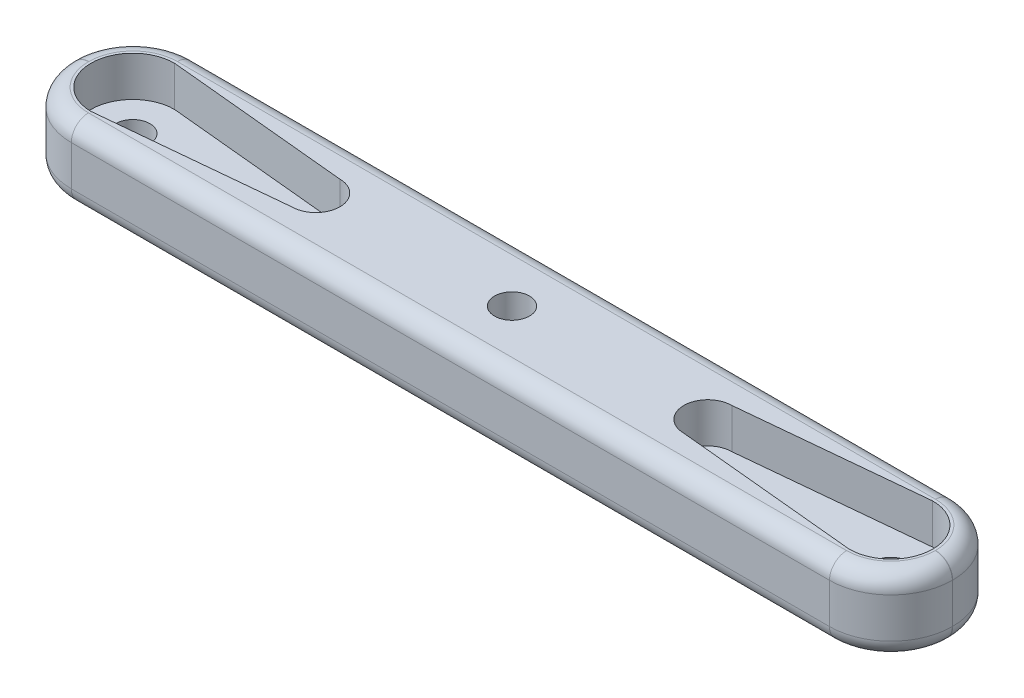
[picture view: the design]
from build123d import *

# Parameters (mm, degrees)
SKETCH1_W           = 77
SKETCH1_H           = 10.77
BOSS_EXTRUDE1_DEPTH = 6.5
SKETCH2_R           = 1.5
CUT_EXTRUDE1_DEPTH  = 3.5
SKETCH4_R           = 1.5
CUT_EXTRUDE4_DEPTH  = 40.414441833
CUT_EXTRUDE5_DEPTH  = 3.5
CUT_EXTRUDE6_DEPTH  = 40.414441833
SKETCH5_R           = 1.525
CUT_EXTRUDE7_DEPTH  = 40.414441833
FILLET1_R           = 1.5
SKETCH6_W           = 0.628205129
SKETCH6_H           = 2.557692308
SKETCH6_W_2         = 0.246794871
SKETCH6_H_2         = 2.009615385
CUT_EXTRUDE8_DEPTH  = 1


with BuildPart() as part:
    # Sketch1 → Boss-Extrude1 (new body)
    with BuildSketch(Plane(origin=(0, 0, 0), x_dir=(1, 0, 0), z_dir=(0, 1, 0))):
        Rectangle(SKETCH1_W, SKETCH1_H)
    extrude(amount=BOSS_EXTRUDE1_DEPTH)

    # Sketch2 → Cut-Extrude1 (cut)
    # profile 1 of 2: a face of its own
    with BuildSketch(Plane(origin=(0, 6.5, 0), x_dir=(1, 0, 0), z_dir=(0, 1, 0))):
        with BuildLine():
            ThreePointArc((-32.429387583, -3.597128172), (-30.312222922, -2.335050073), (-29.48, -0.015))
            ThreePointArc((-29.48, -0.015), (-30.312222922, 2.305050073), (-32.429387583, 3.567128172))
            Line((-32.429387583, 3.567128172), (-33.13, 3.635))
            ThreePointArc((-33.13, 3.635), (-36.78, -0.015), (-33.13, -3.665))
            Line((-33.13, -3.665), (-32.429387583, -3.597128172))
        make_face()
        with Locations(Location((-33.13, -0.015, 0), (0, 0, 270))):
            Circle(SKETCH2_R, mode=Mode.SUBTRACT)
    # profile 2 of 2: a face of its own
    with BuildSketch(Plane(origin=(0, 6.5, 0), x_dir=(1, 0, 0), z_dir=(0, 1, 0))):
        with BuildLine():
            ThreePointArc((32.429387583, 3.567128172), (30.312222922, 2.305050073), (29.48, -0.015))
            ThreePointArc((29.48, -0.015), (30.312222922, -2.335050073), (32.429387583, -3.597128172))
            Line((32.429387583, -3.597128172), (33.13, -3.665))
            ThreePointArc((33.13, -3.665), (36.78, -0.015), (33.13, 3.635))
            Line((33.13, 3.635), (32.429387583, 3.567128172))
        make_face()
        with Locations(Location((33.13, -0.015, 0), (0, 0, 270))):
            Circle(SKETCH2_R, mode=Mode.SUBTRACT)
    extrude(amount=-CUT_EXTRUDE1_DEPTH, mode=Mode.SUBTRACT)

    # Sketch4 → Cut-Extrude4 (cut, through all)
    with BuildSketch(Plane(origin=(0, 6.5, 0), x_dir=(1, 0, 0), z_dir=(0, 1, 0))):
        with Locations(Location((-33.13, -0.015, 0), (0, 0, 270))):
            Circle(SKETCH4_R)
        with Locations(Location((33.13, -0.015, 0), (0, 0, 270))):
            Circle(SKETCH4_R)
    extrude(amount=-CUT_EXTRUDE4_DEPTH, mode=Mode.SUBTRACT)

    # Sketch2_5 → Cut-Extrude5 (cut)
    with BuildSketch(Plane(origin=(0, 6.5, 0), x_dir=(1, 0, 0), z_dir=(0, 1, 0))):
        with BuildLine():
            ThreePointArc((-32.429387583, 3.567128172), (-29.48, -0.015), (-32.429387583, -3.597128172))
            Line((-32.429387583, -3.597128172), (-17.13, -2.115))
            ThreePointArc((-17.13, -2.115), (-15.03, -0.015), (-17.13, 2.085))
            Line((-17.13, 2.085), (-32.429387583, 3.567128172))
        make_face()
        with BuildLine():
            ThreePointArc((32.429387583, -3.597128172), (29.48, -0.015), (32.429387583, 3.567128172))
            Line((32.429387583, 3.567128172), (17.13, 2.085))
            ThreePointArc((17.13, 2.085), (15.03, -0.015), (17.13, -2.115))
            Line((17.13, -2.115), (32.429387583, -3.597128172))
        make_face()
    extrude(amount=-CUT_EXTRUDE5_DEPTH, mode=Mode.SUBTRACT)

    # Sketch2_6 → Cut-Extrude6 (cut, through all)
    with BuildSketch(Plane(origin=(0, 6.5, 0), x_dir=(1, 0, 0), z_dir=(0, 1, 0))):
        with BuildLine():
            Line((-38.5, 5.385), (-38.5, 0.015))
            ThreePointArc((-38.5, 0.015), (-36.927163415, 3.812163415), (-33.13, 5.385))
            Line((-33.13, 5.385), (-38.5, 5.385))
        make_face()
        with BuildLine():
            Line((-38.5, -5.385), (-33.13, -5.385))
            ThreePointArc((-33.13, -5.385), (-36.927163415, -3.812163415), (-38.5, -0.015))
            Line((-38.5, -0.015), (-38.5, -5.385))
        make_face()
        with BuildLine():
            ThreePointArc((38.5, -0.015), (36.927163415, -3.812163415), (33.13, -5.385))
            Line((33.13, -5.385), (38.5, -5.385))
            Line((38.5, -5.385), (38.5, -0.015))
        make_face()
        with BuildLine():
            ThreePointArc((33.13, 5.385), (36.927163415, 3.812163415), (38.5, 0.015))
            Line((38.5, 0.015), (38.5, 5.385))
            Line((38.5, 5.385), (33.13, 5.385))
        make_face()
    extrude(amount=-CUT_EXTRUDE6_DEPTH, mode=Mode.SUBTRACT)

    # Sketch5 → Cut-Extrude7 (cut, through all)
    with BuildSketch(Plane(origin=(0, 6.5, 0), x_dir=(1, 0, 0), z_dir=(0, 1, 0))):
        with Locations(Location((0, 0, 0), (0, 0, 270))):
            Circle(SKETCH5_R)
    extrude(amount=-CUT_EXTRUDE7_DEPTH, mode=Mode.SUBTRACT)

    # Fillet1
    fillet1_edges = [part.edges().sort_by_distance(p)[0] for p in [
        (-36.927163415, 6.5, 3.812163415),
        (-36.927163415, 0, 3.812163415),
        (-36.927163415, 6.5, -3.812163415),
        (-36.927163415, 0, -3.812163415),
        (38.5, 0, 0),
        (0, 0, 5.385),
        (-38.5, 0, 0),
        (0, 0, -5.385),
        (0, 6.5, 5.385),
        (-38.5, 6.5, 0),
        (0, 6.5, -5.385),
        (38.5, 6.5, 0),
        (36.927163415, 6.5, -3.812163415),
        (36.927163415, 0, -3.812163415),
        (36.927163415, 0, 3.812163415),
        (36.927163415, 6.5, 3.812163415),
    ]]
    fillet(fillet1_edges, radius=FILLET1_R)

    # Sketch6 → Cut-Extrude8 (cut)
    # profile 1 of 21: a face of its own
    with BuildSketch(Plane.XZ):
        Polygon((-30.093520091, 1.617771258), (-29.441476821, 1.617771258), (-28.642899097, -0.823534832), (-27.838712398, 1.617771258), (-27.192979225, 1.617771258), (-26.60123243, -1.882228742), (-27.237149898, -1.882228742), (-27.610847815, 0.328408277), (-28.338612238, -1.882228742), (-28.951392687, -1.882228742), (-29.674950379, 0.328408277), (-30.047947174, -1.882228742), (-30.684565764, -1.882228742), align=None)
    # profile 2 of 21: a face of its own
    with BuildSketch(Plane.XZ):
        with BuildLine():
            add(Edge.make_bspline(
                [(-25.839814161, 1.752386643), (-25.812738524, 1.75105821), (-25.759572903, 1.748449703), (-25.683405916, 1.723022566), (-25.613500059, 1.683115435), (-25.551701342, 1.6283619), (-25.500302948, 1.562976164), (-25.461032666, 1.489772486), (-25.439156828, 1.408665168), (-25.436118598, 1.352637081), (-25.434565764, 1.324001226)],
                knots=[0, 0, 0, 0, 0.989868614, 1.943702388, 2.910836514, 3.924849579, 4.949916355, 5.946401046, 6.950409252, 8, 8, 8, 8], degree=3))
            add(Edge.make_bspline(
                [(-25.434565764, 1.324001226), (-25.43606304, 1.295576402), (-25.438980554, 1.240189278), (-25.461536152, 1.160183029), (-25.499230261, 1.087014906), (-25.55104495, 1.02260027), (-25.612173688, 0.968728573), (-25.680552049, 0.928096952), (-25.755989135, 0.904084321), (-25.808329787, 0.901257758), (-25.834906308, 0.89982254)],
                knots=[0, 0, 0, 0, 1.05296456, 2.051751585, 3.055639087, 4.085634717, 5.099016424, 6.062201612, 7.016062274, 8, 8, 8, 8], degree=3))
            add(Edge.make_bspline(
                [(-25.834906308, 0.89982254), (-25.862218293, 0.901146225), (-25.915846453, 0.903745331), (-25.992638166, 0.929231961), (-26.063476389, 0.968824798), (-26.125007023, 1.024697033), (-26.176994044, 1.090547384), (-26.214548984, 1.165455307), (-26.238040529, 1.247117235), (-26.240828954, 1.303975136), (-26.242258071, 1.333115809)],
                knots=[0, 0, 0, 0, 0.989065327, 1.942068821, 2.907541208, 3.917690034, 4.939857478, 5.938239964, 6.943311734, 8, 8, 8, 8], degree=3))
            add(Edge.make_bspline(
                [(-26.242258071, 1.333115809), (-26.240702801, 1.361057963), (-26.237647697, 1.415946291), (-26.21564082, 1.495250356), (-26.177271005, 1.567223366), (-26.126242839, 1.631412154), (-26.064986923, 1.68514433), (-25.995123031, 1.723839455), (-25.91946865, 1.748216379), (-25.866639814, 1.750982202), (-25.839814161, 1.752386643)],
                knots=[0, 0, 0, 0, 1.038616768, 2.040212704, 3.031499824, 4.052181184, 5.074969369, 6.039807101, 7.004644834, 8, 8, 8, 8], degree=3))
        make_face()
    # profile 3 of 21: a face of its own
    with BuildSketch(Plane.XZ):
        with Locations((-25.838411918, -0.603382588)):
            Rectangle(SKETCH6_W, SKETCH6_H)
    # profile 4 of 21: a face of its own
    with BuildSketch(Plane.XZ):
        with BuildLine():
            Line((-22.473027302, 0.15382895), (-22.993259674, -0.132228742))
            add(Edge.make_bspline(
                [(-22.993259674, -0.132228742), (-23.01710523, -0.108349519), (-23.062942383, -0.062447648), (-23.136445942, -0.004343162), (-23.20863609, 0.043765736), (-23.282488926, 0.079267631), (-23.358664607, 0.106003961), (-23.439910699, 0.12371202), (-23.527175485, 0.135372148), (-23.587536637, 0.136447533), (-23.618660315, 0.137002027)],
                knots=[0, 0, 0, 0, 1.150764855, 2.212059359, 3.192108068, 4.105322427, 5.000809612, 5.941206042, 6.938435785, 8, 8, 8, 8], degree=3))
            add(Edge.make_bspline(
                [(-23.618660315, 0.137002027), (-23.647202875, 0.136312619), (-23.703058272, 0.134963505), (-23.78467187, 0.124886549), (-23.862237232, 0.109059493), (-23.935615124, 0.085904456), (-24.004674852, 0.05531539), (-24.069987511, 0.019117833), (-24.130918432, -0.024102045), (-24.186606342, -0.073729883), (-24.236874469, -0.128369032), (-24.281716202, -0.186644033), (-24.318452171, -0.249419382), (-24.350212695, -0.31521963), (-24.37356342, -0.385280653), (-24.390647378, -0.45896672), (-24.400385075, -0.536281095), (-24.401795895, -0.589100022), (-24.402514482, -0.61600278)],
                knots=[0, 0, 0, 0, 1.121765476, 2.195200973, 3.227634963, 4.230038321, 5.213228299, 6.192116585, 7.160777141, 8.14345191, 9.118668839, 10.075979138, 11.027630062, 11.972829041, 12.943187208, 13.923755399, 14.94248691, 16, 16, 16, 16], degree=3))
            add(Edge.make_bspline(
                [(-24.402514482, -0.61600278), (-24.401755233, -0.642203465), (-24.400272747, -0.693362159), (-24.391164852, -0.768526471), (-24.375353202, -0.840079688), (-24.351645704, -0.90764353), (-24.323229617, -0.97184084), (-24.287544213, -1.032161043), (-24.245580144, -1.088867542), (-24.197116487, -1.141467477), (-24.143431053, -1.188774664), (-24.085553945, -1.230551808), (-24.023657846, -1.265971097), (-23.957021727, -1.293767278), (-23.886732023, -1.316415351), (-23.812319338, -1.332541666), (-23.733862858, -1.341492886), (-23.680381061, -1.342997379), (-23.653015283, -1.343767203)],
                knots=[0, 0, 0, 0, 1.070556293, 2.090336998, 3.088792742, 4.058148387, 5.011235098, 5.952916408, 6.915475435, 7.888633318, 8.869583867, 9.83422472, 10.800707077, 11.776204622, 12.778807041, 13.814557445, 14.881744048, 16, 16, 16, 16], degree=3))
            add(Edge.make_bspline(
                [(-23.653015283, -1.343767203), (-23.619321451, -1.34299619), (-23.553555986, -1.341491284), (-23.457952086, -1.328727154), (-23.367990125, -1.307619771), (-23.283660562, -1.278405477), (-23.205081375, -1.240207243), (-23.132454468, -1.19355095), (-23.065033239, -1.138780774), (-23.025716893, -1.096080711), (-23.005879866, -1.074536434)],
                knots=[0, 0, 0, 0, 1.116373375, 2.178998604, 3.189797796, 4.174590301, 5.13072713, 6.078291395, 7.030403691, 8, 8, 8, 8], degree=3))
            Line((-23.005879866, -1.074536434), (-22.517899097, -1.409672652))
            add(Edge.make_bspline(
                [(-22.517899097, -1.409672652), (-22.55172358, -1.45102736), (-22.618473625, -1.532637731), (-22.734933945, -1.63783052), (-22.860280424, -1.7282145), (-22.997034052, -1.800357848), (-23.143203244, -1.857738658), (-23.299930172, -1.898301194), (-23.466949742, -1.92217863), (-23.581655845, -1.925433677), (-23.640395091, -1.927100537)],
                knots=[0, 0, 0, 0, 0.997876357, 1.969233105, 2.924898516, 3.881013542, 4.852507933, 5.855329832, 6.901747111, 8, 8, 8, 8], degree=3))
            add(Edge.make_bspline(
                [(-23.640395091, -1.927100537), (-23.693264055, -1.925878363), (-23.796522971, -1.923491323), (-23.947020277, -1.905211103), (-24.088570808, -1.874420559), (-24.221465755, -1.831658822), (-24.345583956, -1.776266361), (-24.460522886, -1.707559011), (-24.567057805, -1.627447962), (-24.663266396, -1.535554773), (-24.749106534, -1.435528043), (-24.824045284, -1.330183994), (-24.888855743, -1.221410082), (-24.939699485, -1.107395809), (-24.981252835, -0.98991828), (-25.009316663, -0.867573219), (-25.027826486, -0.741368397), (-25.029747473, -0.655799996), (-25.03071961, -0.612497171)],
                knots=[0, 0, 0, 0, 1.183377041, 2.311265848, 3.387807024, 4.421911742, 5.431260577, 6.423665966, 7.413571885, 8.409103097, 9.395976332, 10.359992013, 11.300391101, 12.225292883, 13.150239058, 14.085544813, 15.031169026, 16, 16, 16, 16], degree=3))
            add(Edge.make_bspline(
                [(-25.03071961, -0.612497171), (-25.030198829, -0.582327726), (-25.029167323, -0.522571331), (-25.020361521, -0.433826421), (-25.006662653, -0.346587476), (-24.986074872, -0.261466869), (-24.960755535, -0.178051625), (-24.929976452, -0.096358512), (-24.892523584, -0.01680908), (-24.850744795, 0.061273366), (-24.803128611, 0.135827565), (-24.751180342, 0.206820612), (-24.694973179, 0.273817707), (-24.633846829, 0.336194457), (-24.568227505, 0.39439719), (-24.49906914, 0.449606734), (-24.424133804, 0.498975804), (-24.346026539, 0.545391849), (-24.264074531, 0.586711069), (-24.179219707, 0.622375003), (-24.092117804, 0.652676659), (-24.002560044, 0.677039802), (-23.910930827, 0.697119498), (-23.816414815, 0.709862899), (-23.719793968, 0.718819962), (-23.654438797, 0.719827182), (-23.621464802, 0.720335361)],
                knots=[0, 0, 0, 0, 1.00272354, 1.986087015, 2.96193297, 3.936200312, 4.894695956, 5.858592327, 6.835334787, 7.815655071, 8.800643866, 9.773423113, 10.738352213, 11.705312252, 12.673769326, 13.65298065, 14.64420052, 15.654211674, 16.672258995, 17.692438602, 18.712115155, 19.735602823, 20.776372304, 21.827874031, 22.90408564, 24, 24, 24, 24], degree=3))
            add(Edge.make_bspline(
                [(-23.621464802, 0.720335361), (-23.590836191, 0.719989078), (-23.530430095, 0.719306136), (-23.441223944, 0.712165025), (-23.354451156, 0.700035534), (-23.26996406, 0.683988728), (-23.187506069, 0.664103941), (-23.108182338, 0.637598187), (-23.03090838, 0.607515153), (-22.931378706, 0.562092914), (-22.814051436, 0.494292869), (-22.685257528, 0.39705266), (-22.570422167, 0.283295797), (-22.505664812, 0.197213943), (-22.473027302, 0.15382895)],
                knots=[0, 0, 0, 0, 0.826738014, 1.630502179, 2.413926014, 3.191023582, 3.95155221, 4.701751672, 5.446919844, 6.189438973, 7.653650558, 9.094719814, 10.535747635, 12, 12, 12, 12], degree=3))
        make_face()
    # profile 5 of 21: a face of its own
    with BuildSketch(Plane.XZ):
        with BuildLine():
            Line((-21.934565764, 0.675463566), (-21.396104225, 0.675463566))
            Line((-21.396104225, 0.675463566), (-21.396104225, 0.36065988))
            add(Edge.make_bspline(
                [(-21.396104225, 0.36065988), (-21.380872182, 0.38863657), (-21.351100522, 0.443318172), (-21.296407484, 0.516717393), (-21.233573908, 0.57853217), (-21.164857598, 0.630055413), (-21.090050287, 0.670212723), (-21.011155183, 0.698829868), (-20.928847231, 0.717427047), (-20.872699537, 0.719358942), (-20.844321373, 0.720335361)],
                knots=[0, 0, 0, 0, 1.09866127, 2.147379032, 3.14564304, 4.131443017, 5.102343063, 6.064490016, 7.021754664, 8, 8, 8, 8], degree=3))
            add(Edge.make_bspline(
                [(-20.844321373, 0.720335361), (-20.823715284, 0.719370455), (-20.781753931, 0.717405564), (-20.717798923, 0.705983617), (-20.652921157, 0.685330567), (-20.610225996, 0.66673524), (-20.588411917, 0.657234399)],
                knots=[0, 0, 0, 0, 0.931404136, 1.896671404, 2.925354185, 4, 4, 4, 4], degree=3))
            Line((-20.588411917, 0.657234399), (-20.783323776, 0.125082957))
            add(Edge.make_bspline(
                [(-20.783323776, 0.125082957), (-20.800746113, 0.133500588), (-20.8334934, 0.149322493), (-20.881036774, 0.167993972), (-20.924184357, 0.179386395), (-20.951539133, 0.181086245), (-20.9642132, 0.181873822)],
                knots=[0, 0, 0, 0, 1.214386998, 2.282580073, 3.20428172, 4, 4, 4, 4], degree=3))
            add(Edge.make_bspline(
                [(-20.9642132, 0.181873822), (-20.976179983, 0.181351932), (-20.999720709, 0.180325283), (-21.034466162, 0.171527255), (-21.067189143, 0.156355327), (-21.099466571, 0.136918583), (-21.128752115, 0.109900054), (-21.158019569, 0.078621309), (-21.183811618, 0.040003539), (-21.211029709, -0.002980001), (-21.23420494, -0.055591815), (-21.254076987, -0.118399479), (-21.271783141, -0.192129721), (-21.283967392, -0.277174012), (-21.29574396, -0.372709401), (-21.302753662, -0.479437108), (-21.307978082, -0.597019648), (-21.30829752, -0.679096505), (-21.308464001, -0.721872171)],
                knots=[0, 0, 0, 0, 0.544232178, 1.070598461, 1.618251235, 2.182094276, 2.777567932, 3.425210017, 4.127676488, 4.886675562, 5.738955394, 6.734782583, 7.883056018, 9.186093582, 10.642914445, 12.264202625, 14.053029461, 16, 16, 16, 16], degree=3))
            Line((-21.308464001, -0.721872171), (-21.306360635, -0.846671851))
            Line((-21.306360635, -0.846671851), (-21.306360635, -1.882228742))
            Line((-21.306360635, -1.882228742), (-21.934565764, -1.882228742))
            Line((-21.934565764, -1.882228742), (-21.934565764, 0.675463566))
        make_face()
    # profile 6 of 21: a face of its own
    with BuildSketch(Plane.XZ):
        with BuildLine():
            add(Edge.make_bspline(
                [(-19.055759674, 0.720335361), (-19.026059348, 0.719806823), (-18.967239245, 0.718760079), (-18.87963405, 0.710046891), (-18.793560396, 0.695830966), (-18.708523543, 0.677423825), (-18.625313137, 0.651632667), (-18.543492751, 0.62070016), (-18.462330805, 0.585186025), (-18.383841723, 0.542911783), (-18.307458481, 0.497061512), (-18.235042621, 0.4464849), (-18.167195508, 0.391579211), (-18.102657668, 0.333617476), (-18.044436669, 0.270076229), (-17.988811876, 0.204017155), (-17.938788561, 0.133073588), (-17.892474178, 0.058974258), (-17.851240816, -0.017852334), (-17.815437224, -0.096871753), (-17.784363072, -0.1769915), (-17.760032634, -0.259187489), (-17.739889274, -0.342375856), (-17.727177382, -0.427576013), (-17.718140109, -0.513912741), (-17.717126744, -0.57204173), (-17.716617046, -0.601279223)],
                knots=[0, 0, 0, 0, 1.022364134, 2.024744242, 3.027414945, 4.024939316, 5.017584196, 6.023349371, 7.035562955, 8.064994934, 9.090267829, 10.101425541, 11.102933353, 12.093946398, 13.084502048, 14.067315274, 15.065326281, 16.070028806, 17.074376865, 18.064572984, 19.055292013, 20.030201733, 21.013838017, 21.999348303, 22.993720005, 24, 24, 24, 24], degree=3))
            add(Edge.make_bspline(
                [(-17.716617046, -0.601279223), (-17.717154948, -0.630745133), (-17.718224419, -0.689330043), (-17.726850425, -0.776478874), (-17.741120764, -0.862079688), (-17.759598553, -0.946636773), (-17.785293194, -1.029068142), (-17.815314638, -1.110588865), (-17.852167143, -1.190087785), (-17.892910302, -1.268432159), (-17.939522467, -1.343316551), (-17.989502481, -1.414970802), (-18.04489429, -1.481515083), (-18.102649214, -1.545013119), (-18.1655067, -1.603317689), (-18.232463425, -1.657375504), (-18.30293973, -1.707847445), (-18.377442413, -1.753549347), (-18.455017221, -1.793705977), (-18.534355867, -1.829910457), (-18.615922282, -1.860053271), (-18.699547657, -1.884633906), (-18.78528271, -1.903666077), (-18.87293816, -1.916594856), (-18.962325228, -1.925586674), (-19.022550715, -1.926592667), (-19.052955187, -1.927100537)],
                knots=[0, 0, 0, 0, 1.012026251, 2.012137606, 3.004615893, 3.992048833, 4.982446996, 5.968083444, 6.973977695, 7.990229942, 8.999482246, 10.001782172, 10.988562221, 11.971415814, 12.948383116, 13.930088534, 14.925840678, 15.924049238, 16.929462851, 17.924729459, 18.917889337, 19.913673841, 20.916777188, 21.931792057, 22.95587778, 24, 24, 24, 24], degree=3))
            add(Edge.make_bspline(
                [(-19.052955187, -1.927100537), (-19.097412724, -1.92579562), (-19.185039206, -1.92322361), (-19.314092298, -1.905606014), (-19.438069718, -1.875281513), (-19.557173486, -1.833009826), (-19.67155832, -1.778840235), (-19.780225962, -1.71179714), (-19.884257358, -1.633200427), (-19.981850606, -1.543714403), (-20.071259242, -1.445540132), (-20.149368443, -1.340739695), (-20.215689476, -1.230883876), (-20.270162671, -1.115847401), (-20.312204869, -0.995472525), (-20.34256651, -0.870119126), (-20.360205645, -0.739434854), (-20.362755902, -0.65064419), (-20.364052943, -0.605485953)],
                knots=[0, 0, 0, 0, 1.029999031, 2.030143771, 3.011211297, 3.982305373, 4.953580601, 5.938004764, 6.935448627, 7.970290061, 9.001484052, 10.007591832, 10.993831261, 11.969999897, 12.951306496, 13.942897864, 14.953773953, 16, 16, 16, 16], degree=3))
            add(Edge.make_bspline(
                [(-20.364052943, -0.605485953), (-20.362710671, -0.557266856), (-20.360072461, -0.462493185), (-20.339123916, -0.323647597), (-20.30567135, -0.190709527), (-20.257652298, -0.064050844), (-20.196312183, 0.056562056), (-20.121429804, 0.170874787), (-20.032635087, 0.278913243), (-19.964636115, 0.344258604), (-19.930058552, 0.377486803)],
                knots=[0, 0, 0, 0, 1.043912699, 2.05178951, 3.033892, 4.007821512, 4.978932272, 5.95884105, 6.962068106, 8, 8, 8, 8], degree=3))
            add(Edge.make_bspline(
                [(-19.930058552, 0.377486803), (-19.898330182, 0.405029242), (-19.835736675, 0.459364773), (-19.734042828, 0.528280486), (-19.629919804, 0.587802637), (-19.522119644, 0.636740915), (-19.410341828, 0.673639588), (-19.295159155, 0.70049852), (-19.176595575, 0.716996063), (-19.096242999, 0.719216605), (-19.055759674, 0.720335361)],
                knots=[0, 0, 0, 0, 1.048115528, 2.067714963, 3.060638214, 4.039924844, 5.017819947, 5.994373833, 6.98952318, 8, 8, 8, 8], degree=3))
        make_face()
        with BuildLine():
            add(Edge.make_bspline(
                [(-19.041737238, 0.137002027), (-19.066059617, 0.136193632), (-19.113938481, 0.134602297), (-19.184417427, 0.126062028), (-19.251077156, 0.108558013), (-19.315241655, 0.086297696), (-19.375775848, 0.056527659), (-19.43433755, 0.021689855), (-19.487881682, -0.02190537), (-19.538999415, -0.069726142), (-19.585402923, -0.122829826), (-19.624943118, -0.18068625), (-19.660273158, -0.241081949), (-19.687062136, -0.306228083), (-19.709232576, -0.374344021), (-19.724237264, -0.446530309), (-19.734679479, -0.521980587), (-19.735454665, -0.573664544), (-19.735847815, -0.599876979)],
                knots=[0, 0, 0, 0, 1.030650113, 2.02884584, 2.99876339, 3.944280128, 4.900564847, 5.851248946, 6.823638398, 7.81794922, 8.81432732, 9.802856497, 10.78262424, 11.771747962, 12.779760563, 13.812642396, 14.89064281, 16, 16, 16, 16], degree=3))
            add(Edge.make_bspline(
                [(-19.735847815, -0.599876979), (-19.735387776, -0.627013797), (-19.73448872, -0.680047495), (-19.725178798, -0.757483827), (-19.709826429, -0.830970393), (-19.688015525, -0.900393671), (-19.660584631, -0.966251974), (-19.626930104, -1.028175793), (-19.58669676, -1.085792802), (-19.541081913, -1.139032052), (-19.491135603, -1.187357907), (-19.436408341, -1.228829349), (-19.3791919, -1.264862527), (-19.318167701, -1.293802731), (-19.254202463, -1.316146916), (-19.1871063, -1.332598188), (-19.116526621, -1.341461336), (-19.068402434, -1.342988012), (-19.043840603, -1.343767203)],
                knots=[0, 0, 0, 0, 1.141730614, 2.231293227, 3.276944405, 4.297399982, 5.28939179, 6.275415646, 7.257752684, 8.24146775, 9.222424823, 10.176631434, 11.126518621, 12.063689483, 13.012557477, 13.974037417, 14.965980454, 16, 16, 16, 16], degree=3))
            add(Edge.make_bspline(
                [(-19.043840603, -1.343767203), (-19.019266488, -1.343076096), (-18.971086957, -1.341721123), (-18.900424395, -1.331574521), (-18.83298559, -1.315605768), (-18.768474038, -1.293069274), (-18.707411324, -1.26350962), (-18.649563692, -1.227304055), (-18.59442225, -1.185255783), (-18.543805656, -1.13601811), (-18.496950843, -1.082612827), (-18.455861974, -1.024691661), (-18.421526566, -0.962767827), (-18.393365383, -0.89723095), (-18.371511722, -0.828171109), (-18.356413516, -0.755331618), (-18.345965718, -0.678938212), (-18.345208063, -0.626556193), (-18.344822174, -0.599876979)],
                knots=[0, 0, 0, 0, 1.031504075, 2.022346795, 2.991027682, 3.937587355, 4.885570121, 5.833146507, 6.798790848, 7.791235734, 8.792807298, 9.778388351, 10.766749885, 11.760164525, 12.768777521, 13.802286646, 14.880660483, 16, 16, 16, 16], degree=3))
            add(Edge.make_bspline(
                [(-18.344822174, -0.599876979), (-18.345288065, -0.57320709), (-18.346202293, -0.520872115), (-18.355512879, -0.444375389), (-18.370714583, -0.371771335), (-18.3928068, -0.303369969), (-18.420074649, -0.238390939), (-18.453752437, -0.177166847), (-18.4941842, -0.119999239), (-18.540020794, -0.067171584), (-18.59071583, -0.019523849), (-18.644492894, 0.022966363), (-18.702581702, 0.058109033), (-18.763892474, 0.087079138), (-18.828588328, 0.109367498), (-18.896596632, 0.125912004), (-18.968125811, 0.134649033), (-19.016943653, 0.136209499), (-19.041737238, 0.137002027)],
                knots=[0, 0, 0, 0, 1.123894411, 2.205445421, 3.243160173, 4.246488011, 5.231014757, 6.210004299, 7.185865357, 8.177612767, 9.153374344, 10.115157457, 11.061423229, 12.009021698, 12.96873347, 13.94135618, 14.954456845, 16, 16, 16, 16], degree=3))
        make_face(mode=Mode.SUBTRACT)
    # profile 7 of 21: a face of its own
    with BuildSketch(Plane.XZ):
        Polygon((-15.742258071, 1.617771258), (-14.037129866, 1.617771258), (-14.037129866, 0.98956613), (-15.114052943, 0.98956613), (-15.114052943, 0.316489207), (-14.037129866, 0.316489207), (-14.037129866, -0.311715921), (-15.114052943, -0.311715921), (-15.114052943, -1.882228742), (-15.742258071, -1.882228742), align=None)
    # profile 8 of 21: a face of its own
    with BuildSketch(Plane.XZ):
        with BuildLine():
            add(Edge.make_bspline(
                [(-11.764093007, 1.707514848), (-11.703241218, 1.705939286), (-11.583106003, 1.70282877), (-11.406430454, 1.676900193), (-11.236170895, 1.634653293), (-11.072404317, 1.575927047), (-10.915540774, 1.49913085), (-10.765026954, 1.406441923), (-10.621401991, 1.296110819), (-10.486137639, 1.170711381), (-10.361128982, 1.034344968), (-10.252808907, 0.88752228), (-10.160437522, 0.73404764), (-10.08387987, 0.57350981), (-10.025566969, 0.404796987), (-9.984646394, 0.228769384), (-9.958356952, 0.04547708), (-9.955333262, -0.079319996), (-9.953796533, -0.142745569)],
                knots=[0, 0, 0, 0, 1.014329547, 2.002516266, 2.970391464, 3.935626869, 4.897733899, 5.877609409, 6.878433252, 7.912639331, 8.949961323, 9.958554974, 10.949718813, 11.932905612, 12.9188844, 13.919928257, 14.942845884, 16, 16, 16, 16], degree=3))
            add(Edge.make_bspline(
                [(-9.953796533, -0.142745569), (-9.955433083, -0.205456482), (-9.958657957, -0.329030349), (-9.983573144, -0.510633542), (-10.025182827, -0.684775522), (-10.082506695, -0.851850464), (-10.15767588, -1.011049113), (-10.248245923, -1.16338793), (-10.356606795, -1.307453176), (-10.47880615, -1.443167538), (-10.613337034, -1.566357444), (-10.755826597, -1.674918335), (-10.905616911, -1.766908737), (-11.062488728, -1.842286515), (-11.226778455, -1.900784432), (-11.398080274, -1.942058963), (-11.576383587, -1.967142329), (-11.697638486, -1.970346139), (-11.759185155, -1.971972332)],
                knots=[0, 0, 0, 0, 1.051557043, 2.072126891, 3.067553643, 4.050577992, 5.02905126, 6.015227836, 7.017913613, 8.04756643, 9.074058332, 10.072836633, 11.047628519, 12.017157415, 12.98668631, 13.966869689, 14.968021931, 16, 16, 16, 16], degree=3))
            add(Edge.make_bspline(
                [(-11.759185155, -1.971972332), (-11.82355559, -1.970513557), (-11.950034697, -1.967647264), (-12.135137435, -1.940390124), (-12.312481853, -1.899331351), (-12.480578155, -1.838053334), (-12.641138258, -1.761450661), (-12.79298248, -1.667109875), (-12.936059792, -1.555186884), (-13.069549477, -1.428548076), (-13.190491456, -1.289977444), (-13.297246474, -1.143589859), (-13.387296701, -0.990503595), (-13.46064543, -0.830647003), (-13.518470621, -0.665013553), (-13.559259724, -0.49259449), (-13.58335482, -0.313803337), (-13.586711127, -0.192364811), (-13.588411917, -0.130826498)],
                knots=[0, 0, 0, 0, 1.067978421, 2.098431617, 3.099715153, 4.085208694, 5.062210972, 6.048429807, 7.046490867, 8.072918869, 9.098532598, 10.095778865, 11.076610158, 12.041847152, 13.011192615, 13.984257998, 14.978533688, 16, 16, 16, 16], degree=3))
            add(Edge.make_bspline(
                [(-13.588411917, -0.130826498), (-13.587878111, -0.089426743), (-13.586817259, -0.007151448), (-13.57403817, 0.11477634), (-13.555639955, 0.234324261), (-13.52842987, 0.351015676), (-13.49537657, 0.465673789), (-13.452551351, 0.577231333), (-13.403804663, 0.68688005), (-13.346848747, 0.793324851), (-13.283519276, 0.895586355), (-13.214421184, 0.993182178), (-13.139380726, 1.084932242), (-13.058639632, 1.171439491), (-12.971919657, 1.252135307), (-12.880361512, 1.328162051), (-12.782189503, 1.397500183), (-12.679552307, 1.461843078), (-12.573028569, 1.520027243), (-12.463051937, 1.569551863), (-12.351888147, 1.612800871), (-12.238052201, 1.6469349), (-12.122764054, 1.67473671), (-12.004792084, 1.693122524), (-11.885202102, 1.705901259), (-11.804558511, 1.706975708), (-11.764093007, 1.707514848)],
                knots=[0, 0, 0, 0, 1.034744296, 2.056386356, 3.06226378, 4.057406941, 5.050368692, 6.043467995, 7.042652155, 8.049140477, 9.059438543, 10.048523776, 11.036952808, 12.020949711, 13.004946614, 13.997082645, 14.994316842, 16.007702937, 17.024872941, 18.026463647, 19.021641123, 20.005082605, 20.995858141, 21.984425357, 22.988620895, 24, 24, 24, 24], degree=3))
        make_face()
        with BuildLine():
            add(Edge.make_bspline(
                [(-11.773908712, 1.07930972), (-11.814861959, 1.078210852), (-11.895687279, 1.076042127), (-12.014243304, 1.059519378), (-12.128061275, 1.033130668), (-12.236510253, 0.994906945), (-12.340060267, 0.946257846), (-12.438894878, 0.887353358), (-12.531645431, 0.816168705), (-12.619548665, 0.736525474), (-12.698954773, 0.64778461), (-12.769112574, 0.552683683), (-12.827823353, 0.45138151), (-12.876993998, 0.344819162), (-12.914008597, 0.231798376), (-12.940372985, 0.113204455), (-12.957034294, -0.011166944), (-12.959134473, -0.095950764), (-12.960206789, -0.13923996)],
                knots=[0, 0, 0, 0, 1.033739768, 2.040188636, 3.016340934, 3.979330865, 4.937572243, 5.900995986, 6.878200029, 7.884839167, 8.891893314, 9.879764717, 10.863503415, 11.843163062, 12.837761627, 13.859916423, 14.907309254, 16, 16, 16, 16], degree=3))
            add(Edge.make_bspline(
                [(-12.960206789, -0.13923996), (-12.958785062, -0.187214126), (-12.955998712, -0.281235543), (-12.936393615, -0.418391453), (-12.902851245, -0.547921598), (-12.854416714, -0.669192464), (-12.79434519, -0.783550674), (-12.719745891, -0.889594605), (-12.631826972, -0.9879592), (-12.564094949, -1.045388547), (-12.529718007, -1.074536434)],
                knots=[0, 0, 0, 0, 1.078454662, 2.113592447, 3.107694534, 4.079536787, 5.043276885, 6.005368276, 6.987637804, 8, 8, 8, 8], degree=3))
            add(Edge.make_bspline(
                [(-12.529718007, -1.074536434), (-12.501556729, -1.096069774), (-12.44586865, -1.138651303), (-12.356978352, -1.193228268), (-12.265438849, -1.240006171), (-12.170559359, -1.277802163), (-12.072540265, -1.307531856), (-11.971395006, -1.328351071), (-11.867266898, -1.341416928), (-11.796850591, -1.342978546), (-11.76128852, -1.343767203)],
                knots=[0, 0, 0, 0, 1.023928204, 2.024787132, 3.009472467, 3.9914905, 4.972207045, 5.96565515, 6.972602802, 8, 8, 8, 8], degree=3))
            add(Edge.make_bspline(
                [(-11.76128852, -1.343767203), (-11.721039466, -1.342659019), (-11.641848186, -1.34047863), (-11.525499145, -1.324159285), (-11.414033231, -1.29654106), (-11.306758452, -1.258652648), (-11.203984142, -1.209392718), (-11.106212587, -1.148661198), (-11.013272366, -1.077203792), (-10.925481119, -0.996514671), (-10.84523577, -0.90742423), (-10.775224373, -0.811816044), (-10.714646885, -0.711796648), (-10.666498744, -0.60595042), (-10.628021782, -0.495276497), (-10.601974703, -0.37928473), (-10.585172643, -0.258453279), (-10.583071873, -0.176223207), (-10.582001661, -0.134332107)],
                knots=[0, 0, 0, 0, 1.026359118, 2.019393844, 2.989460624, 3.950973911, 4.916101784, 5.890408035, 6.881132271, 7.902007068, 8.92769091, 9.933912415, 10.920395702, 11.90457117, 12.894218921, 13.903490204, 14.931958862, 16, 16, 16, 16], degree=3))
            add(Edge.make_bspline(
                [(-10.582001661, -0.134332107), (-10.583108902, -0.092681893), (-10.585288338, -0.010699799), (-10.601636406, 0.109820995), (-10.629079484, 0.225300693), (-10.66708167, 0.335927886), (-10.715608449, 0.441811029), (-10.775616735, 0.542577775), (-10.846895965, 0.638130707), (-10.927805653, 0.727818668), (-11.015870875, 0.81023616), (-11.11041769, 0.88175956), (-11.208800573, 0.943911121), (-11.313276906, 0.992598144), (-11.421709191, 1.031386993), (-11.534759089, 1.059951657), (-11.652854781, 1.075926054), (-11.733197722, 1.078171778), (-11.773908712, 1.07930972)],
                knots=[0, 0, 0, 0, 1.055025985, 2.07665775, 3.074803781, 4.057872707, 5.035505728, 6.020516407, 7.023567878, 8.050795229, 9.077271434, 10.074415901, 11.050397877, 12.019801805, 12.988065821, 13.964604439, 14.968634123, 16, 16, 16, 16], degree=3))
        make_face(mode=Mode.SUBTRACT)
    # profile 9 of 21: a face of its own
    with BuildSketch(Plane.XZ):
        with BuildLine():
            Line((-9.325591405, -1.882228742), (-9.325591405, 1.617771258))
            Line((-9.325591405, 1.617771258), (-8.764693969, 1.617771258))
            add(Edge.make_bspline(
                [(-8.764693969, 1.617771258), (-8.725427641, 1.617775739), (-8.649448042, 1.617784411), (-8.539829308, 1.613934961), (-8.438167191, 1.608955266), (-8.344785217, 1.603384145), (-8.259524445, 1.593783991), (-8.182514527, 1.583666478), (-8.113601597, 1.57146538), (-8.070996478, 1.560520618), (-8.050951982, 1.555371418)],
                knots=[0, 0, 0, 0, 1.311965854, 2.538629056, 3.664479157, 4.713267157, 5.663616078, 6.530575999, 7.308677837, 8, 8, 8, 8], degree=3))
            add(Edge.make_bspline(
                [(-8.050951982, 1.555371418), (-8.024631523, 1.548108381), (-7.972982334, 1.53385597), (-7.899004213, 1.505072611), (-7.828825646, 1.473077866), (-7.762532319, 1.436577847), (-7.700531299, 1.395131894), (-7.643058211, 1.348411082), (-7.588873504, 1.298290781), (-7.539901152, 1.243374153), (-7.495638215, 1.185344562), (-7.457181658, 1.124217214), (-7.423767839, 1.060926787), (-7.397028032, 0.994676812), (-7.37688009, 0.925772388), (-7.362143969, 0.854507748), (-7.352592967, 0.780657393), (-7.351690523, 0.730414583), (-7.35123243, 0.704910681)],
                knots=[0, 0, 0, 0, 1.099996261, 2.158545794, 3.195537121, 4.207578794, 5.205712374, 6.197378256, 7.190519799, 8.17788031, 9.159561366, 10.129234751, 11.085776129, 12.040971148, 13.00380137, 13.975669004, 14.972423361, 16, 16, 16, 16], degree=3))
            add(Edge.make_bspline(
                [(-7.35123243, 0.704910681), (-7.352430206, 0.672144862), (-7.35478788, 0.607649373), (-7.369848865, 0.512917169), (-7.398090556, 0.42338162), (-7.435044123, 0.337392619), (-7.485289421, 0.255270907), (-7.549091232, 0.177055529), (-7.625416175, 0.100338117), (-7.68396162, 0.054351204), (-7.71441352, 0.030431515)],
                knots=[0, 0, 0, 0, 0.986156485, 1.941127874, 2.875419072, 3.804401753, 4.751181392, 5.761612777, 6.835722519, 8, 8, 8, 8], degree=3))
            add(Edge.make_bspline(
                [(-7.71441352, 0.030431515), (-7.689736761, 0.017834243), (-7.641352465, -0.00686552), (-7.572660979, -0.047464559), (-7.509060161, -0.090646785), (-7.450264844, -0.135543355), (-7.397508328, -0.1840575), (-7.348612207, -0.233393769), (-7.305988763, -0.286378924), (-7.267873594, -0.341124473), (-7.234744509, -0.398423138), (-7.205892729, -0.458178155), (-7.181522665, -0.52059366), (-7.160885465, -0.585352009), (-7.145494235, -0.65267594), (-7.135458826, -0.72258953), (-7.12777509, -0.794854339), (-7.127177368, -0.844079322), (-7.126873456, -0.869107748)],
                knots=[0, 0, 0, 0, 1.164658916, 2.283573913, 3.35186032, 4.395461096, 5.390182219, 6.362969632, 7.312859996, 8.245001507, 9.165155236, 10.092416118, 11.032087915, 11.979892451, 12.947605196, 13.931445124, 14.948243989, 16, 16, 16, 16], degree=3))
            add(Edge.make_bspline(
                [(-7.126873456, -0.869107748), (-7.12884564, -0.91691061), (-7.132737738, -1.011249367), (-7.161194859, -1.149760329), (-7.210530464, -1.281081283), (-7.276778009, -1.404690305), (-7.35840773, -1.517009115), (-7.4522585, -1.615399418), (-7.557385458, -1.698684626), (-7.654377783, -1.754895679), (-7.738268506, -1.792618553), (-7.807753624, -1.815941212), (-7.882379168, -1.837547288), (-7.963512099, -1.852719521), (-8.049681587, -1.866606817), (-8.14172779, -1.875181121), (-8.239478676, -1.880991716), (-8.30661821, -1.881808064), (-8.341216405, -1.882228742)],
                knots=[0, 0, 0, 0, 1.284142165, 2.534249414, 3.780121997, 5.041676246, 6.291546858, 7.49970053, 8.684500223, 9.883330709, 10.50184324, 11.153274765, 11.851151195, 12.587658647, 13.369265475, 14.195992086, 15.070362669, 16, 16, 16, 16], degree=3))
            Line((-8.341216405, -1.882228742), (-9.325591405, -1.882228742))
        make_face()
        with BuildLine():
            Line((-8.697386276, 0.98956613), (-8.697386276, 0.226745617))
            Line((-8.697386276, 0.226745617), (-8.530519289, 0.226745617))
            add(Edge.make_bspline(
                [(-8.530519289, 0.226745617), (-8.507840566, 0.226943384), (-8.464060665, 0.227325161), (-8.40082524, 0.232242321), (-8.342026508, 0.2406313), (-8.287887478, 0.252336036), (-8.237903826, 0.267199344), (-8.192394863, 0.285083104), (-8.151560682, 0.306903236), (-8.104120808, 0.339405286), (-8.05397344, 0.387233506), (-8.009829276, 0.456331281), (-7.983828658, 0.535793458), (-7.980932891, 0.591836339), (-7.979437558, 0.620776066)],
                knots=[0, 0, 0, 0, 1.065314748, 2.056525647, 2.977365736, 3.853934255, 4.656397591, 5.425096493, 6.14721249, 6.826394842, 8.123232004, 9.372140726, 10.643011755, 12, 12, 12, 12], degree=3))
            add(Edge.make_bspline(
                [(-7.979437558, 0.620776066), (-7.980634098, 0.647882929), (-7.982947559, 0.700292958), (-8.009126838, 0.773881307), (-8.049788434, 0.839095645), (-8.097795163, 0.883729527), (-8.143002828, 0.914213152), (-8.181712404, 0.934285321), (-8.22419907, 0.952253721), (-8.271285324, 0.965992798), (-8.322702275, 0.976302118), (-8.378200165, 0.983873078), (-8.437874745, 0.989026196), (-8.479092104, 0.989382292), (-8.500371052, 0.98956613)],
                knots=[0, 0, 0, 0, 1.347982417, 2.606269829, 3.849316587, 5.153353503, 5.842674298, 6.568177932, 7.326619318, 8.142485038, 9.012069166, 9.942760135, 10.937925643, 12, 12, 12, 12], degree=3))
            Line((-8.500371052, 0.98956613), (-8.697386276, 0.98956613))
        make_face(mode=Mode.SUBTRACT)
        with BuildLine():
            Line((-8.697386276, -0.356587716), (-8.697386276, -1.254023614))
            Line((-8.697386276, -1.254023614), (-8.516496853, -1.254023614))
            add(Edge.make_bspline(
                [(-8.516496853, -1.254023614), (-8.480734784, -1.253819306), (-8.411977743, -1.2534265), (-8.313483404, -1.248680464), (-8.223927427, -1.240126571), (-8.1435471, -1.229447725), (-8.072219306, -1.214979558), (-8.01018515, -1.196585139), (-7.956593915, -1.176348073), (-7.911766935, -1.151352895), (-7.875145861, -1.122264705), (-7.84209918, -1.092535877), (-7.815154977, -1.058240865), (-7.79383622, -1.020851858), (-7.775384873, -0.981297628), (-7.764256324, -0.938033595), (-7.755783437, -0.892342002), (-7.755317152, -0.860738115), (-7.755078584, -0.844568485)],
                knots=[0, 0, 0, 0, 1.753078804, 3.370512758, 4.83203934, 6.162291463, 7.344201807, 8.395507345, 9.331626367, 10.147333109, 10.898971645, 11.62040215, 12.321813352, 13.025280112, 13.727906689, 14.453419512, 15.208716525, 16, 16, 16, 16], degree=3))
            add(Edge.make_bspline(
                [(-7.755078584, -0.844568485), (-7.755604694, -0.82607826), (-7.756629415, -0.790064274), (-7.764998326, -0.737425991), (-7.780207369, -0.688284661), (-7.799363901, -0.641383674), (-7.826021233, -0.598402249), (-7.857702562, -0.557852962), (-7.895981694, -0.521108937), (-7.939028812, -0.485947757), (-7.989239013, -0.455162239), (-8.046635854, -0.42845035), (-8.111531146, -0.406141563), (-8.18412591, -0.388379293), (-8.264101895, -0.373304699), (-8.352042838, -0.364303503), (-8.447216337, -0.357608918), (-8.51321119, -0.356935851), (-8.547346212, -0.356587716)],
                knots=[0, 0, 0, 0, 0.845221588, 1.646264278, 2.427170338, 3.19324141, 3.95557735, 4.731569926, 5.540061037, 6.376114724, 7.268642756, 8.224665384, 9.265483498, 10.400594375, 11.639216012, 12.983232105, 14.439614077, 16, 16, 16, 16], degree=3))
            Line((-8.547346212, -0.356587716), (-8.697386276, -0.356587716))
        make_face(mode=Mode.SUBTRACT)
    # profile 10 of 21: a face of its own
    with BuildSketch(Plane.XZ):
        with BuildLine():
            add(Edge.make_bspline(
                [(-4.853836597, 1.707514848), (-4.792984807, 1.705939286), (-4.672849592, 1.70282877), (-4.496174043, 1.676900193), (-4.325914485, 1.634653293), (-4.162147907, 1.575927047), (-4.005284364, 1.49913085), (-3.854770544, 1.406441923), (-3.711145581, 1.296110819), (-3.575881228, 1.170711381), (-3.450872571, 1.034344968), (-3.342552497, 0.88752228), (-3.250181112, 0.73404764), (-3.17362346, 0.57350981), (-3.115310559, 0.404796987), (-3.074389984, 0.228769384), (-3.048100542, 0.04547708), (-3.045076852, -0.079319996), (-3.043540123, -0.142745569)],
                knots=[0, 0, 0, 0, 1.014329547, 2.002516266, 2.970391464, 3.935626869, 4.897733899, 5.877609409, 6.878433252, 7.912639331, 8.949961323, 9.958554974, 10.949718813, 11.932905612, 12.9188844, 13.919928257, 14.942845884, 16, 16, 16, 16], degree=3))
            add(Edge.make_bspline(
                [(-3.043540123, -0.142745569), (-3.045176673, -0.205456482), (-3.048401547, -0.329030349), (-3.073316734, -0.510633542), (-3.114926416, -0.684775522), (-3.172250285, -0.851850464), (-3.24741947, -1.011049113), (-3.337989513, -1.16338793), (-3.446350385, -1.307453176), (-3.56854974, -1.443167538), (-3.703080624, -1.566357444), (-3.845570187, -1.674918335), (-3.9953605, -1.766908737), (-4.152232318, -1.842286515), (-4.316522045, -1.900784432), (-4.487823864, -1.942058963), (-4.666127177, -1.967142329), (-4.787382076, -1.970346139), (-4.848928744, -1.971972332)],
                knots=[0, 0, 0, 0, 1.051557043, 2.072126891, 3.067553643, 4.050577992, 5.02905126, 6.015227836, 7.017913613, 8.04756643, 9.074058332, 10.072836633, 11.047628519, 12.017157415, 12.98668631, 13.966869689, 14.968021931, 16, 16, 16, 16], degree=3))
            add(Edge.make_bspline(
                [(-4.848928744, -1.971972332), (-4.91329918, -1.970513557), (-5.039778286, -1.967647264), (-5.224881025, -1.940390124), (-5.402225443, -1.899331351), (-5.570321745, -1.838053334), (-5.730881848, -1.761450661), (-5.88272607, -1.667109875), (-6.025803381, -1.555186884), (-6.159293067, -1.428548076), (-6.280235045, -1.289977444), (-6.386990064, -1.143589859), (-6.477040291, -0.990503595), (-6.55038902, -0.830647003), (-6.608214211, -0.665013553), (-6.649003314, -0.49259449), (-6.67309841, -0.313803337), (-6.676454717, -0.192364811), (-6.678155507, -0.130826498)],
                knots=[0, 0, 0, 0, 1.067978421, 2.098431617, 3.099715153, 4.085208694, 5.062210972, 6.048429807, 7.046490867, 8.072918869, 9.098532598, 10.095778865, 11.076610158, 12.041847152, 13.011192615, 13.984257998, 14.978533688, 16, 16, 16, 16], degree=3))
            add(Edge.make_bspline(
                [(-6.678155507, -0.130826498), (-6.677621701, -0.089426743), (-6.676560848, -0.007151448), (-6.663781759, 0.11477634), (-6.645383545, 0.234324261), (-6.618173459, 0.351015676), (-6.58512016, 0.465673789), (-6.542294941, 0.577231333), (-6.493548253, 0.68688005), (-6.436592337, 0.793324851), (-6.373262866, 0.895586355), (-6.304164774, 0.993182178), (-6.229124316, 1.084932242), (-6.148383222, 1.171439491), (-6.061663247, 1.252135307), (-5.970105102, 1.328162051), (-5.871933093, 1.397500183), (-5.769295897, 1.461843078), (-5.662772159, 1.520027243), (-5.552795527, 1.569551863), (-5.441631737, 1.612800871), (-5.327795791, 1.6469349), (-5.212507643, 1.67473671), (-5.094535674, 1.693122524), (-4.974945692, 1.705901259), (-4.894302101, 1.706975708), (-4.853836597, 1.707514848)],
                knots=[0, 0, 0, 0, 1.034744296, 2.056386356, 3.06226378, 4.057406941, 5.050368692, 6.043467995, 7.042652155, 8.049140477, 9.059438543, 10.048523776, 11.036952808, 12.020949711, 13.004946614, 13.997082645, 14.994316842, 16.007702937, 17.024872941, 18.026463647, 19.021641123, 20.005082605, 20.995858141, 21.984425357, 22.988620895, 24, 24, 24, 24], degree=3))
        make_face()
        with BuildLine():
            add(Edge.make_bspline(
                [(-4.863652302, 1.07930972), (-4.904605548, 1.078210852), (-4.985430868, 1.076042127), (-5.103986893, 1.059519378), (-5.217804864, 1.033130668), (-5.326253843, 0.994906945), (-5.429803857, 0.946257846), (-5.528638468, 0.887353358), (-5.621389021, 0.816168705), (-5.709292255, 0.736525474), (-5.788698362, 0.64778461), (-5.858856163, 0.552683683), (-5.917566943, 0.45138151), (-5.966737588, 0.344819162), (-6.003752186, 0.231798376), (-6.030116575, 0.113204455), (-6.046777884, -0.011166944), (-6.048878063, -0.095950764), (-6.049950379, -0.13923996)],
                knots=[0, 0, 0, 0, 1.033739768, 2.040188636, 3.016340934, 3.979330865, 4.937572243, 5.900995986, 6.878200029, 7.884839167, 8.891893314, 9.879764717, 10.863503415, 11.843163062, 12.837761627, 13.859916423, 14.907309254, 16, 16, 16, 16], degree=3))
            add(Edge.make_bspline(
                [(-6.049950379, -0.13923996), (-6.048528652, -0.187214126), (-6.045742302, -0.281235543), (-6.026137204, -0.418391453), (-5.992594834, -0.547921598), (-5.944160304, -0.669192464), (-5.88408878, -0.783550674), (-5.80948948, -0.889594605), (-5.721570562, -0.9879592), (-5.653838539, -1.045388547), (-5.619461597, -1.074536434)],
                knots=[0, 0, 0, 0, 1.078454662, 2.113592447, 3.107694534, 4.079536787, 5.043276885, 6.005368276, 6.987637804, 8, 8, 8, 8], degree=3))
            add(Edge.make_bspline(
                [(-5.619461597, -1.074536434), (-5.591300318, -1.096069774), (-5.53561224, -1.138651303), (-5.446721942, -1.193228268), (-5.355182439, -1.240006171), (-5.260302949, -1.277802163), (-5.162283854, -1.307531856), (-5.061138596, -1.328351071), (-4.957010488, -1.341416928), (-4.886594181, -1.342978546), (-4.85103211, -1.343767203)],
                knots=[0, 0, 0, 0, 1.023928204, 2.024787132, 3.009472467, 3.9914905, 4.972207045, 5.96565515, 6.972602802, 8, 8, 8, 8], degree=3))
            add(Edge.make_bspline(
                [(-4.85103211, -1.343767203), (-4.810783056, -1.342659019), (-4.731591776, -1.34047863), (-4.615242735, -1.324159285), (-4.50377682, -1.29654106), (-4.396502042, -1.258652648), (-4.293727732, -1.209392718), (-4.195956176, -1.148661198), (-4.103015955, -1.077203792), (-4.015224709, -0.996514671), (-3.934979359, -0.90742423), (-3.864967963, -0.811816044), (-3.804390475, -0.711796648), (-3.756242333, -0.60595042), (-3.717765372, -0.495276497), (-3.691718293, -0.37928473), (-3.674916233, -0.258453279), (-3.672815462, -0.176223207), (-3.671745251, -0.134332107)],
                knots=[0, 0, 0, 0, 1.026359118, 2.019393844, 2.989460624, 3.950973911, 4.916101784, 5.890408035, 6.881132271, 7.902007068, 8.92769091, 9.933912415, 10.920395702, 11.90457117, 12.894218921, 13.903490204, 14.931958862, 16, 16, 16, 16], degree=3))
            add(Edge.make_bspline(
                [(-3.671745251, -0.134332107), (-3.672852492, -0.092681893), (-3.675031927, -0.010699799), (-3.691379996, 0.109820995), (-3.718823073, 0.225300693), (-3.75682526, 0.335927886), (-3.805352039, 0.441811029), (-3.865360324, 0.542577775), (-3.936639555, 0.638130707), (-4.017549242, 0.727818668), (-4.105614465, 0.81023616), (-4.20016128, 0.88175956), (-4.298544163, 0.943911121), (-4.403020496, 0.992598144), (-4.511452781, 1.031386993), (-4.624502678, 1.059951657), (-4.742598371, 1.075926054), (-4.822941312, 1.078171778), (-4.863652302, 1.07930972)],
                knots=[0, 0, 0, 0, 1.055025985, 2.07665775, 3.074803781, 4.057872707, 5.035505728, 6.020516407, 7.023567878, 8.050795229, 9.077271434, 10.074415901, 11.050397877, 12.019801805, 12.988065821, 13.964604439, 14.968634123, 16, 16, 16, 16], degree=3))
        make_face(mode=Mode.SUBTRACT)
    # profile 11 of 21: a face of its own
    with BuildSketch(Plane.XZ):
        with BuildLine():
            Line((5.611857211, -0.586978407), (5.844329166, -0.44760541))
            add(Edge.make_bspline(
                [(5.844329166, -0.44760541), (5.865950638, -0.483798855), (5.907376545, -0.5531441), (5.976481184, -0.646846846), (6.048085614, -0.72648854), (6.122720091, -0.791605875), (6.19992905, -0.842872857), (6.280216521, -0.879174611), (6.363311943, -0.901815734), (6.419862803, -0.904565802), (6.448095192, -0.905938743)],
                knots=[0, 0, 0, 0, 1.272034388, 2.437168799, 3.508375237, 4.49857839, 5.41946034, 6.295179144, 7.148887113, 8, 8, 8, 8], degree=3))
            add(Edge.make_bspline(
                [(6.448095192, -0.905938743), (6.472206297, -0.905267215), (6.520006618, -0.903935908), (6.590376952, -0.891143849), (6.658719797, -0.871491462), (6.723626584, -0.843346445), (6.784201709, -0.809294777), (6.837321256, -0.768165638), (6.883243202, -0.722117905), (6.920807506, -0.670745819), (6.949627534, -0.615496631), (6.971778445, -0.558786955), (6.984071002, -0.499725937), (6.985922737, -0.459960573), (6.986857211, -0.43989307)],
                knots=[0, 0, 0, 0, 1.095163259, 2.171163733, 3.241058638, 4.321873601, 5.38011039, 6.391990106, 7.366004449, 8.327778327, 9.272591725, 10.192022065, 11.087607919, 12, 12, 12, 12], degree=3))
            add(Edge.make_bspline(
                [(6.986857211, -0.43989307), (6.985698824, -0.416996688), (6.983343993, -0.37045169), (6.963440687, -0.301780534), (6.932130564, -0.233822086), (6.90324563, -0.191785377), (6.888249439, -0.169961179)],
                knots=[0, 0, 0, 0, 0.938893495, 1.908633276, 2.914225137, 4, 4, 4, 4], degree=3))
            add(Edge.make_bspline(
                [(6.888249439, -0.169961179), (6.875936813, -0.154210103), (6.850087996, -0.12114269), (6.805649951, -0.071921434), (6.753505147, -0.021149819), (6.695438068, 0.033110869), (6.629333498, 0.088336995), (6.55726188, 0.14716207), (6.477383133, 0.207349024), (6.4213621, 0.247713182), (6.39245617, 0.268540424)],
                knots=[0, 0, 0, 0, 0.722233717, 1.516239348, 2.393582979, 3.351407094, 4.387010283, 5.505090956, 6.712668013, 8, 8, 8, 8], degree=3))
            add(Edge.make_bspline(
                [(6.39245617, 0.268540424), (6.36352303, 0.289148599), (6.30820507, 0.328549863), (6.230844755, 0.387026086), (6.161666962, 0.440489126), (6.100979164, 0.489442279), (6.048808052, 0.533892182), (6.004742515, 0.573411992), (5.969905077, 0.609070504), (5.950532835, 0.632202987), (5.941835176, 0.642588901)],
                knots=[0, 0, 0, 0, 1.452282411, 2.77665338, 3.964542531, 5.026858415, 5.96415736, 6.766646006, 7.446254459, 8, 8, 8, 8], degree=3))
            add(Edge.make_bspline(
                [(5.941835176, 0.642588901), (5.929678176, 0.65877543), (5.905769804, 0.690608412), (5.8742108, 0.740363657), (5.847387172, 0.791296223), (5.826359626, 0.843542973), (5.808652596, 0.896370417), (5.796742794, 0.950467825), (5.789285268, 1.005592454), (5.788521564, 1.042688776), (5.788139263, 1.061258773)],
                knots=[0, 0, 0, 0, 1.068054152, 2.10047183, 3.106115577, 4.101338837, 5.06977816, 6.043150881, 7.020423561, 8, 8, 8, 8], degree=3))
            add(Edge.make_bspline(
                [(5.788139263, 1.061258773), (5.789164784, 1.090353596), (5.791193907, 1.14792136), (5.808354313, 1.232017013), (5.835440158, 1.31230634), (5.873386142, 1.38799446), (5.922302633, 1.457110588), (5.978910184, 1.520449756), (6.046333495, 1.573696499), (6.120310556, 1.620220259), (6.20128342, 1.656634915), (6.286133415, 1.684104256), (6.374995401, 1.699668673), (6.435183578, 1.701902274), (6.465723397, 1.703035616)],
                knots=[0, 0, 0, 0, 1.005424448, 1.989358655, 2.955360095, 3.929531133, 4.905563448, 5.876582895, 6.856512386, 7.866279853, 8.892233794, 9.918561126, 10.94386622, 12, 12, 12, 12], degree=3))
            add(Edge.make_bspline(
                [(6.465723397, 1.703035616), (6.498129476, 1.701917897), (6.562574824, 1.69969511), (6.657370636, 1.680368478), (6.74863977, 1.648389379), (6.822059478, 1.612098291), (6.879520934, 1.575852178), (6.923342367, 1.542836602), (6.967748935, 1.504827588), (7.013098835, 1.461723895), (7.058623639, 1.413130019), (7.104999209, 1.359378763), (7.152333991, 1.300798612), (7.182785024, 1.258979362), (7.198395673, 1.237540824)],
                knots=[0, 0, 0, 0, 1.286793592, 2.559021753, 3.825965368, 5.121522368, 5.803751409, 6.523245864, 7.299691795, 8.125521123, 9.008227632, 9.944561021, 10.946284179, 12, 12, 12, 12], degree=3))
            Line((7.198395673, 1.237540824), (6.975288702, 1.068420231))
            add(Edge.make_bspline(
                [(6.975288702, 1.068420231), (6.961816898, 1.085775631), (6.935873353, 1.119198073), (6.896485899, 1.166004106), (6.859361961, 1.208759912), (6.822786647, 1.245896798), (6.788691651, 1.279448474), (6.755599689, 1.308173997), (6.723986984, 1.332354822), (6.684137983, 1.358160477), (6.634074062, 1.383740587), (6.571229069, 1.405386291), (6.505554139, 1.418393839), (6.460823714, 1.42011368), (6.438179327, 1.420984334)],
                knots=[0, 0, 0, 0, 1.181633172, 2.275549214, 3.290209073, 4.226197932, 5.078386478, 5.862611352, 6.581680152, 7.217281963, 8.414376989, 9.595101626, 10.782541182, 12, 12, 12, 12], degree=3))
            add(Edge.make_bspline(
                [(6.438179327, 1.420984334), (6.40977063, 1.420032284), (6.354987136, 1.418196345), (6.277209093, 1.398144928), (6.207206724, 1.366573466), (6.14705828, 1.322325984), (6.096979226, 1.269902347), (6.060753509, 1.209576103), (6.038949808, 1.142961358), (6.03628916, 1.096492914), (6.034934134, 1.072827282)],
                knots=[0, 0, 0, 0, 1.14458467, 2.207223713, 3.21896685, 4.227309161, 5.202851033, 6.127160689, 7.046193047, 8, 8, 8, 8], degree=3))
            add(Edge.make_bspline(
                [(6.034934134, 1.072827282), (6.03524302, 1.058093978), (6.035861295, 1.028603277), (6.04448435, 0.985034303), (6.055562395, 0.941575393), (6.073117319, 0.898421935), (6.097352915, 0.854819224), (6.129178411, 0.810016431), (6.169260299, 0.763618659), (6.199963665, 0.733441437), (6.216174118, 0.717508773)],
                knots=[0, 0, 0, 0, 0.858281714, 1.717966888, 2.583508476, 3.4729293, 4.427298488, 5.488583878, 6.674047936, 8, 8, 8, 8], degree=3))
            add(Edge.make_bspline(
                [(6.216174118, 0.717508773), (6.222193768, 0.712136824), (6.236495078, 0.699374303), (6.262640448, 0.678480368), (6.297166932, 0.652706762), (6.339172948, 0.620816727), (6.389433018, 0.58382415), (6.447952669, 0.542202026), (6.514079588, 0.494599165), (6.56100395, 0.461318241), (6.585815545, 0.443720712)],
                knots=[0, 0, 0, 0, 0.420754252, 0.999615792, 1.744751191, 2.668019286, 3.750313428, 4.999500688, 6.413464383, 8, 8, 8, 8], degree=3))
            add(Edge.make_bspline(
                [(6.585815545, 0.443720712), (6.615661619, 0.422002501), (6.673454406, 0.379948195), (6.755685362, 0.316764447), (6.830244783, 0.254969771), (6.897394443, 0.194958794), (6.957797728, 0.137186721), (7.010784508, 0.080958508), (7.056894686, 0.026676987), (7.1065355, -0.042915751), (7.157259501, -0.128386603), (7.200820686, -0.233105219), (7.228287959, -0.3382309), (7.231879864, -0.4088877), (7.233652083, -0.44374924)],
                knots=[0, 0, 0, 0, 1.163667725, 2.253281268, 3.268753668, 4.215851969, 5.092017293, 5.902905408, 6.650798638, 7.335211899, 8.59617414, 9.77448103, 10.901945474, 12, 12, 12, 12], degree=3))
            add(Edge.make_bspline(
                [(7.233652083, -0.44374924), (7.23313576, -0.46840367), (7.232113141, -0.517233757), (7.220358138, -0.588934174), (7.203135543, -0.658572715), (7.177177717, -0.725288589), (7.145495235, -0.790302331), (7.105293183, -0.851908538), (7.058694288, -0.911470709), (7.005239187, -0.967400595), (6.946745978, -1.018744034), (6.884923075, -1.064416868), (6.819669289, -1.102499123), (6.751338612, -1.133574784), (6.679915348, -1.157879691), (6.605423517, -1.175489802), (6.52774033, -1.186297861), (6.474939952, -1.187419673), (6.448095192, -1.187990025)],
                knots=[0, 0, 0, 0, 0.983748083, 1.948392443, 2.894712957, 3.844097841, 4.80183111, 5.778335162, 6.776009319, 7.81870978, 8.863265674, 9.881300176, 10.883814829, 11.87499822, 12.874611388, 13.892143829, 14.928324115, 16, 16, 16, 16], degree=3))
            add(Edge.make_bspline(
                [(6.448095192, -1.187990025), (6.427324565, -1.187588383), (6.386044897, -1.186790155), (6.324987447, -1.179733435), (6.265163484, -1.169749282), (6.207323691, -1.153898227), (6.150722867, -1.134666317), (6.095607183, -1.110986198), (6.041949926, -1.082608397), (5.989450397, -1.050162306), (5.938242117, -1.01240265), (5.888805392, -0.968423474), (5.839518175, -0.91943772), (5.791835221, -0.864115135), (5.744792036, -0.803349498), (5.699316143, -0.736572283), (5.654466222, -0.664147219), (5.626325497, -0.613181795), (5.611857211, -0.586978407)],
                knots=[0, 0, 0, 0, 0.915332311, 1.819136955, 2.706846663, 3.586547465, 4.459518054, 5.340707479, 6.227863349, 7.133153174, 8.059268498, 9.028702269, 10.047606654, 11.120612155, 12.245963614, 13.433783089, 14.680604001, 16, 16, 16, 16], degree=3))
        make_face()
    # profile 12 of 21: a face of its own
    with BuildSketch(Plane.XZ):
        with BuildLine():
            Line((7.727241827, 0.89213818), (7.974036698, 0.89213818))
            Line((7.974036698, 0.89213818), (7.974036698, 0.520293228))
            add(Edge.make_bspline(
                [(7.974036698, 0.520293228), (8.00024615, 0.554030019), (8.051178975, 0.61959072), (8.138962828, 0.704440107), (8.231619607, 0.775999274), (8.331533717, 0.83208555), (8.43715233, 0.874373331), (8.548042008, 0.905628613), (8.665143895, 0.924046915), (8.745205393, 0.926263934), (8.786035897, 0.92739459)],
                knots=[0, 0, 0, 0, 1.0828784, 2.104357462, 3.088488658, 4.04616522, 5.001424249, 5.969181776, 6.964304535, 8, 8, 8, 8], degree=3))
            add(Edge.make_bspline(
                [(8.786035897, 0.92739459), (8.821700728, 0.926362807), (8.89219414, 0.924323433), (8.995958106, 0.910516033), (9.095881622, 0.886852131), (9.191399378, 0.852751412), (9.283534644, 0.810593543), (9.370923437, 0.757387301), (9.454926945, 0.695782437), (9.533432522, 0.624885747), (9.605970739, 0.548177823), (9.668707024, 0.465660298), (9.722820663, 0.380046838), (9.766561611, 0.290010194), (9.800825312, 0.19625937), (9.825193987, 0.098415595), (9.839696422, -0.003158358), (9.841642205, -0.072224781), (9.842626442, -0.107160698)],
                knots=[0, 0, 0, 0, 1.041296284, 2.058176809, 3.050446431, 4.034000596, 5.01514041, 6.003636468, 7.015969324, 8.052561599, 9.08815499, 10.094063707, 11.074456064, 12.040834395, 13.011057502, 13.983766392, 14.980127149, 16, 16, 16, 16], degree=3))
            add(Edge.make_bspline(
                [(9.842626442, -0.107160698), (9.84166356, -0.142833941), (9.839764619, -0.213186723), (9.8250364, -0.316498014), (9.801498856, -0.41588095), (9.767667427, -0.511170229), (9.723949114, -0.60230024), (9.670752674, -0.689205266), (9.607984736, -0.771857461), (9.536248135, -0.84913474), (9.458420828, -0.920319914), (9.375231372, -0.982578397), (9.287970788, -1.034860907), (9.197085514, -1.078533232), (9.101797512, -1.111448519), (9.002551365, -1.135191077), (8.899401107, -1.149832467), (8.829235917, -1.15175915), (8.793748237, -1.152733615)],
                knots=[0, 0, 0, 0, 1.038740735, 2.04854663, 3.033179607, 4.009277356, 4.987731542, 5.972001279, 6.972200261, 8.005528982, 9.039189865, 10.040446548, 11.026516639, 11.997840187, 12.972163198, 13.956796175, 14.96660207, 16, 16, 16, 16], degree=3))
            add(Edge.make_bspline(
                [(8.793748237, -1.152733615), (8.753812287, -1.151716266), (8.674927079, -1.149706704), (8.559586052, -1.129341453), (8.448582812, -1.098905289), (8.343147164, -1.05435608), (8.242443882, -0.997583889), (8.147042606, -0.928354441), (8.056436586, -0.846812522), (8.001901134, -0.784951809), (7.974036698, -0.753344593)],
                knots=[0, 0, 0, 0, 1.014726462, 2.004382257, 2.969841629, 3.936926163, 4.907207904, 5.903978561, 6.929055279, 8, 8, 8, 8], degree=3))
            Line((7.974036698, -0.753344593), (7.974036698, -1.85786182))
            Line((7.974036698, -1.85786182), (7.727241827, -1.85786182))
            Line((7.727241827, -1.85786182), (7.727241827, 0.89213818))
        make_face()
        with BuildLine():
            add(Edge.make_bspline(
                [(8.783832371, 0.680599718), (8.755877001, 0.680096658), (8.700840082, 0.679106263), (8.620169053, 0.667341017), (8.542465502, 0.650261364), (8.468512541, 0.624402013), (8.397601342, 0.592660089), (8.33027807, 0.552995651), (8.266589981, 0.506126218), (8.206697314, 0.452949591), (8.152590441, 0.394355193), (8.104690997, 0.331821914), (8.064456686, 0.265428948), (8.031062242, 0.195794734), (8.005649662, 0.122373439), (7.987613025, 0.045583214), (7.976274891, -0.034659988), (7.974790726, -0.089311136), (7.974036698, -0.117076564)],
                knots=[0, 0, 0, 0, 1.05670511, 2.080379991, 3.077984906, 4.06214886, 5.038337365, 6.01289324, 7.01187578, 8.025460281, 9.038092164, 10.024533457, 11.000252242, 11.969694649, 12.940728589, 13.933144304, 14.949937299, 16, 16, 16, 16], degree=3))
            add(Edge.make_bspline(
                [(7.974036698, -0.117076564), (7.975286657, -0.153524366), (7.977735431, -0.224928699), (7.997643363, -0.32925908), (8.030042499, -0.427985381), (8.076029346, -0.520276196), (8.134131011, -0.605119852), (8.204136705, -0.681091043), (8.285412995, -0.747712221), (8.376608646, -0.803828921), (8.474368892, -0.849390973), (8.576343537, -0.882009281), (8.681130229, -0.902101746), (8.751976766, -0.904652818), (8.787688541, -0.905938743)],
                knots=[0, 0, 0, 0, 1.03728447, 2.032128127, 3.01272805, 3.987917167, 4.958271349, 5.931593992, 6.91984656, 7.941419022, 8.973179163, 9.983609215, 10.983593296, 12, 12, 12, 12], degree=3))
            add(Edge.make_bspline(
                [(8.787688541, -0.905938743), (8.82268093, -0.904715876), (8.892134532, -0.902288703), (8.994401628, -0.881280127), (9.093787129, -0.849187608), (9.188214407, -0.802390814), (9.276861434, -0.745041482), (9.356911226, -0.676244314), (9.426845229, -0.596502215), (9.486452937, -0.50770982), (9.534484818, -0.41250059), (9.570572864, -0.313986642), (9.591401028, -0.212515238), (9.594352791, -0.144159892), (9.59583157, -0.109915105)],
                knots=[0, 0, 0, 0, 1.00104056, 1.986885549, 2.97790532, 3.984399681, 4.995088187, 5.994304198, 6.996462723, 8.023150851, 9.048424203, 10.043036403, 11.019596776, 12, 12, 12, 12], degree=3))
            add(Edge.make_bspline(
                [(9.59583157, -0.109915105), (9.594688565, -0.075457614), (9.59241146, -0.00681109), (9.569981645, 0.094359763), (9.536274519, 0.193271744), (9.487120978, 0.287180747), (9.428819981, 0.375788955), (9.358304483, 0.45400986), (9.2792489, 0.522501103), (9.190707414, 0.579084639), (9.095682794, 0.624094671), (8.995649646, 0.657003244), (8.891115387, 0.676782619), (8.819907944, 0.67931616), (8.783832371, 0.680599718)],
                knots=[0, 0, 0, 0, 0.983928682, 1.960191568, 2.949917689, 3.96440592, 4.982380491, 5.975291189, 6.965713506, 7.964880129, 8.970154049, 9.96478489, 10.968906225, 12, 12, 12, 12], degree=3))
        make_face(mode=Mode.SUBTRACT)
    # profile 13 of 21: a face of its own
    with BuildSketch(Plane.XZ):
        with BuildLine():
            Line((10.265703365, 0.89213818), (10.512498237, 0.89213818))
            Line((10.512498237, 0.89213818), (10.512498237, 0.596314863))
            add(Edge.make_bspline(
                [(10.512498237, 0.596314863), (10.530717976, 0.623858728), (10.565563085, 0.676536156), (10.623480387, 0.746204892), (10.682804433, 0.803888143), (10.743819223, 0.849855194), (10.806973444, 0.884279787), (10.870881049, 0.909495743), (10.93654749, 0.924406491), (10.980674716, 0.926397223), (11.002782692, 0.92739459)],
                knots=[0, 0, 0, 0, 1.2804753, 2.448899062, 3.506932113, 4.484331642, 5.4025378, 6.288909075, 7.142734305, 8, 8, 8, 8], degree=3))
            add(Edge.make_bspline(
                [(11.002782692, 0.92739459), (11.019931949, 0.926459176), (11.055217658, 0.924534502), (11.10863255, 0.911011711), (11.163666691, 0.889421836), (11.19913571, 0.869118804), (11.217626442, 0.858534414)],
                knots=[0, 0, 0, 0, 0.901110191, 1.854092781, 2.881294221, 4, 4, 4, 4], degree=3))
            Line((11.217626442, 0.858534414), (11.082109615, 0.644792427))
            add(Edge.make_bspline(
                [(11.082109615, 0.644792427), (11.070238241, 0.65008835), (11.047704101, 0.660141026), (11.014739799, 0.67203832), (10.98434732, 0.679043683), (10.964984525, 0.680104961), (10.955957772, 0.680599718)],
                knots=[0, 0, 0, 0, 1.180555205, 2.24091978, 3.179933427, 4, 4, 4, 4], degree=3))
            add(Edge.make_bspline(
                [(10.955957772, 0.680599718), (10.936153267, 0.679279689), (10.895757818, 0.676587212), (10.836448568, 0.655421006), (10.778897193, 0.621222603), (10.733190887, 0.583295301), (10.697800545, 0.546722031), (10.672547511, 0.514784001), (10.649382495, 0.478972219), (10.627248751, 0.439898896), (10.607082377, 0.396896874), (10.588260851, 0.350395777), (10.571243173, 0.300341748), (10.561539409, 0.265469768), (10.55656875, 0.24760693)],
                knots=[0, 0, 0, 0, 1.125678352, 2.296057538, 3.5422874, 4.923748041, 5.663163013, 6.437101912, 7.23742474, 8.08941207, 8.991984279, 9.93940061, 10.944477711, 12, 12, 12, 12], degree=3))
            add(Edge.make_bspline(
                [(10.55656875, 0.24760693), (10.552850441, 0.231674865), (10.544614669, 0.196386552), (10.536607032, 0.137184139), (10.528695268, 0.067236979), (10.523119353, -0.01364963), (10.517950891, -0.105273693), (10.515035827, -0.207774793), (10.512597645, -0.32125814), (10.512532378, -0.400595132), (10.512498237, -0.442096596)],
                knots=[0, 0, 0, 0, 0.566838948, 1.255505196, 2.06880316, 3.007127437, 4.065329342, 5.249902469, 6.561414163, 8, 8, 8, 8], degree=3))
            Line((10.512498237, -0.442096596), (10.512498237, -1.117477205))
            Line((10.512498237, -1.117477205), (10.265703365, -1.117477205))
            Line((10.265703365, -1.117477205), (10.265703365, 0.89213818))
        make_face()
    # profile 14 of 21: a face of its own
    with BuildSketch(Plane.XZ):
        with BuildLine():
            add(Edge.make_bspline(
                [(11.551460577, 1.738292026), (11.566775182, 1.737581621), (11.59676412, 1.73619051), (11.640130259, 1.724277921), (11.679617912, 1.704085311), (11.714643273, 1.676994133), (11.744698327, 1.645133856), (11.765740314, 1.608000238), (11.779264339, 1.567882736), (11.78089749, 1.539899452), (11.781729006, 1.525651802)],
                knots=[0, 0, 0, 0, 1.055194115, 2.066272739, 3.074728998, 4.095836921, 5.109056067, 6.073838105, 7.019297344, 8, 8, 8, 8], degree=3))
            add(Edge.make_bspline(
                [(11.781729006, 1.525651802), (11.780878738, 1.511774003), (11.779197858, 1.484339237), (11.76575076, 1.444917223), (11.744519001, 1.408299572), (11.714662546, 1.376501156), (11.679612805, 1.349424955), (11.640131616, 1.329228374), (11.596763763, 1.317316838), (11.566775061, 1.315925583), (11.551460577, 1.315215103)],
                knots=[0, 0, 0, 0, 0.96129708, 1.900370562, 2.859976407, 3.87933698, 4.906634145, 5.921202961, 6.938410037, 8, 8, 8, 8], degree=3))
            add(Edge.make_bspline(
                [(11.551460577, 1.315215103), (11.536321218, 1.315898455), (11.506854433, 1.317228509), (11.464137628, 1.329462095), (11.424986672, 1.349431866), (11.389893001, 1.376323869), (11.360640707, 1.40849486), (11.339349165, 1.444894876), (11.325933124, 1.484344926), (11.324248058, 1.511775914), (11.323395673, 1.525651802)],
                knots=[0, 0, 0, 0, 1.054934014, 2.053291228, 3.073705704, 4.106921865, 5.123545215, 6.088680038, 7.033164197, 8, 8, 8, 8], degree=3))
            add(Edge.make_bspline(
                [(11.323395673, 1.525651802), (11.324229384, 1.539897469), (11.325866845, 1.567876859), (11.339359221, 1.608022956), (11.360463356, 1.644936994), (11.38991237, 1.677171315), (11.424981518, 1.704078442), (11.46413896, 1.724044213), (11.506854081, 1.736278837), (11.536321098, 1.737608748), (11.551460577, 1.738292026)],
                knots=[0, 0, 0, 0, 0.98631895, 1.937192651, 2.907499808, 3.917963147, 4.944918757, 5.95915025, 6.951458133, 8, 8, 8, 8], degree=3))
        make_face()
    # profile 15 of 21: a face of its own
    with BuildSketch(Plane.XZ):
        with Locations((11.552562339, -0.112669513)):
            Rectangle(SKETCH6_W_2, SKETCH6_H_2)
    # profile 16 of 21: a face of its own
    with BuildSketch(Plane.XZ):
        with BuildLine():
            Line((12.27531875, 0.89213818), (12.522113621, 0.89213818))
            Line((12.522113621, 0.89213818), (12.522113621, 0.529658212))
            add(Edge.make_bspline(
                [(12.522113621, 0.529658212), (12.548464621, 0.562534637), (12.599599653, 0.626332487), (12.684758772, 0.710184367), (12.774757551, 0.779284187), (12.86904484, 0.834365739), (12.967748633, 0.875888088), (13.070267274, 0.905875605), (13.177214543, 0.923856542), (13.249943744, 0.926206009), (13.286737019, 0.92739459)],
                knots=[0, 0, 0, 0, 1.12780773, 2.188550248, 3.19190651, 4.159438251, 5.104880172, 6.052711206, 7.014878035, 8, 8, 8, 8], degree=3))
            add(Edge.make_bspline(
                [(13.286737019, 0.92739459), (13.323925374, 0.926023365), (13.396711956, 0.923339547), (13.502687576, 0.902112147), (13.601666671, 0.865855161), (13.693296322, 0.816188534), (13.775896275, 0.754426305), (13.84843723, 0.682472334), (13.908436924, 0.599708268), (13.948663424, 0.522925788), (13.975162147, 0.454813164), (13.991844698, 0.396476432), (14.006011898, 0.331483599), (14.018293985, 0.260031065), (14.026604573, 0.181618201), (14.033159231, 0.096566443), (14.037856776, 0.00490334), (14.038043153, -0.058493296), (14.038139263, -0.091185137)],
                knots=[0, 0, 0, 0, 1.235846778, 2.418850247, 3.575807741, 4.728682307, 5.871620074, 6.994088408, 8.11269785, 9.256955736, 9.865816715, 10.540099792, 11.271859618, 12.076849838, 12.949306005, 13.892391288, 14.913166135, 16, 16, 16, 16], degree=3))
            Line((14.038139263, -0.091185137), (14.038139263, -1.117477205))
            Line((14.038139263, -1.117477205), (13.791344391, -1.117477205))
            Line((13.791344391, -1.117477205), (13.791344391, -0.172164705))
            add(Edge.make_bspline(
                [(13.791344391, -0.172164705), (13.791192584, -0.144804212), (13.790902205, -0.092468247), (13.78998634, -0.017535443), (13.787778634, 0.050418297), (13.784676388, 0.111230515), (13.780135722, 0.164842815), (13.775403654, 0.211364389), (13.769616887, 0.250736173), (13.764460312, 0.274437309), (13.762147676, 0.285066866)],
                knots=[0, 0, 0, 0, 1.430800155, 2.736877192, 3.918605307, 4.986035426, 5.920637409, 6.731861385, 7.431261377, 8, 8, 8, 8], degree=3))
            add(Edge.make_bspline(
                [(13.762147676, 0.285066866), (13.753799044, 0.316268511), (13.737730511, 0.376322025), (13.698025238, 0.457780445), (13.647885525, 0.527079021), (13.586680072, 0.583789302), (13.515000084, 0.627923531), (13.433044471, 0.658545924), (13.341604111, 0.677698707), (13.277289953, 0.679605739), (13.243768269, 0.680599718)],
                knots=[0, 0, 0, 0, 1.084156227, 2.086665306, 3.027808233, 3.945421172, 4.874247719, 5.839848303, 6.874090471, 8, 8, 8, 8], degree=3))
            add(Edge.make_bspline(
                [(13.243768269, 0.680599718), (13.223915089, 0.680225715), (13.184626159, 0.679485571), (13.126365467, 0.672059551), (13.069853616, 0.659913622), (13.014523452, 0.643516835), (12.961481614, 0.620996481), (12.909023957, 0.59543769), (12.859125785, 0.563578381), (12.810723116, 0.528071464), (12.765691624, 0.488723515), (12.723790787, 0.447202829), (12.686439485, 0.402986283), (12.652599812, 0.356786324), (12.623388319, 0.307968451), (12.597889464, 0.257003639), (12.576254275, 0.203824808), (12.565503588, 0.166915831), (12.560124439, 0.148448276)],
                knots=[0, 0, 0, 0, 1.023777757, 2.026029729, 3.023749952, 4.003683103, 4.997618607, 5.993177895, 7.010360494, 8.046726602, 9.087585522, 10.09234134, 11.086953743, 12.070360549, 13.043493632, 14.017870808, 15.008233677, 16, 16, 16, 16], degree=3))
            add(Edge.make_bspline(
                [(12.560124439, 0.148448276), (12.557029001, 0.134890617), (12.550290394, 0.105376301), (12.543012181, 0.0569414), (12.536406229, 0.000912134), (12.53087719, -0.062646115), (12.527494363, -0.133955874), (12.523805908, -0.212712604), (12.522463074, -0.299230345), (12.522233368, -0.359464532), (12.522113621, -0.390864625)],
                knots=[0, 0, 0, 0, 0.615963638, 1.340920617, 2.168419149, 3.115676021, 4.16674242, 5.331190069, 6.6087489, 8, 8, 8, 8], degree=3))
            Line((12.522113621, -0.390864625), (12.522113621, -1.117477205))
            Line((12.522113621, -1.117477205), (12.27531875, -1.117477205))
            Line((12.27531875, -1.117477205), (12.27531875, 0.89213818))
        make_face()
    # profile 17 of 21: a face of its own
    with BuildSketch(Plane.XZ):
        with BuildLine():
            Line((16.365062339, 0.89213818), (16.611857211, 0.89213818))
            Line((16.611857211, 0.89213818), (16.611857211, -0.702663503))
            add(Edge.make_bspline(
                [(16.611857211, -0.702663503), (16.611639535, -0.736635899), (16.611219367, -0.802210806), (16.608193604, -0.897029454), (16.601813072, -0.98460995), (16.594577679, -1.065351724), (16.584169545, -1.138880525), (16.571459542, -1.205415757), (16.557131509, -1.265021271), (16.544544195, -1.301733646), (16.538589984, -1.319099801)],
                knots=[0, 0, 0, 0, 1.307562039, 2.523909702, 3.650326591, 4.686913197, 5.643429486, 6.506965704, 7.293745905, 8, 8, 8, 8], degree=3))
            add(Edge.make_bspline(
                [(16.538589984, -1.319099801), (16.529798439, -1.341673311), (16.512478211, -1.386145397), (16.480039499, -1.449186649), (16.44371286, -1.508544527), (16.402221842, -1.563888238), (16.355754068, -1.614939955), (16.305404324, -1.662808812), (16.25019203, -1.706482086), (16.190148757, -1.745206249), (16.126658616, -1.780081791), (16.059758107, -1.810289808), (15.989824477, -1.8366009), (15.916200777, -1.856308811), (15.840041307, -1.873386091), (15.760450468, -1.884499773), (15.677893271, -1.89206389), (15.621757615, -1.892763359), (15.593277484, -1.89311823)],
                knots=[0, 0, 0, 0, 0.981931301, 1.934503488, 2.87077864, 3.801706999, 4.735015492, 5.667491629, 6.616593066, 7.585388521, 8.561939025, 9.551802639, 10.560317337, 11.588439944, 12.640189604, 13.723962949, 14.845264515, 16, 16, 16, 16], degree=3))
            add(Edge.make_bspline(
                [(15.593277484, -1.89311823), (15.551725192, -1.892445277), (15.470562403, -1.891130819), (15.352229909, -1.875816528), (15.239845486, -1.854166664), (15.134894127, -1.821398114), (15.038039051, -1.781297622), (14.94994172, -1.73525873), (14.871392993, -1.68246713), (14.800581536, -1.622359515), (14.736670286, -1.550888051), (14.676541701, -1.466660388), (14.618665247, -1.368393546), (14.584747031, -1.2962707), (14.566985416, -1.258502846)],
                knots=[0, 0, 0, 0, 1.157897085, 2.2616841, 3.32207898, 4.345638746, 5.321241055, 6.241986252, 7.112515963, 7.955008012, 8.825025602, 9.77857164, 10.836726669, 12, 12, 12, 12], degree=3))
            Line((14.566985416, -1.258502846), (14.813780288, -1.258502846))
            add(Edge.make_bspline(
                [(14.813780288, -1.258502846), (14.833629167, -1.290014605), (14.872431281, -1.351616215), (14.944990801, -1.431376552), (15.024510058, -1.49953991), (15.113672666, -1.554469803), (15.212849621, -1.59588464), (15.322100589, -1.625408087), (15.442314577, -1.643083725), (15.52600746, -1.645214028), (15.569589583, -1.646323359)],
                knots=[0, 0, 0, 0, 0.997731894, 1.950442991, 2.880492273, 3.800895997, 4.748200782, 5.754801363, 6.83083817, 8, 8, 8, 8], degree=3))
            add(Edge.make_bspline(
                [(15.569589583, -1.646323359), (15.612620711, -1.64519967), (15.695580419, -1.643033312), (15.814876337, -1.625400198), (15.92377236, -1.595878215), (16.021641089, -1.554543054), (16.107327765, -1.503903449), (16.181194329, -1.447331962), (16.241022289, -1.383546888), (16.281261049, -1.324789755), (16.306273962, -1.272442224), (16.322202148, -1.22737947), (16.335145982, -1.176423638), (16.345972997, -1.119745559), (16.354907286, -1.057264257), (16.360566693, -0.988836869), (16.364656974, -0.914618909), (16.364924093, -0.863160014), (16.365062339, -0.836527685)],
                knots=[0, 0, 0, 0, 1.570740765, 3.028230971, 4.391408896, 5.680370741, 6.894727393, 8.017376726, 9.065722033, 10.075533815, 10.603371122, 11.180248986, 11.817768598, 12.521299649, 13.286540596, 14.121245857, 15.027658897, 16, 16, 16, 16], degree=3))
            Line((16.365062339, -0.836527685), (16.365062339, -0.732411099))
            add(Edge.make_bspline(
                [(16.365062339, -0.732411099), (16.34001289, -0.762222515), (16.290354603, -0.821320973), (16.204595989, -0.898762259), (16.110925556, -0.965458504), (16.009502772, -1.02015886), (15.90281201, -1.063908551), (15.792008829, -1.094506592), (15.6780865, -1.114275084), (15.600888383, -1.116402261), (15.561877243, -1.117477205)],
                knots=[0, 0, 0, 0, 1.012485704, 2.007162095, 2.997754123, 3.998611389, 4.999708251, 5.992315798, 6.98544096, 8, 8, 8, 8], degree=3))
            add(Edge.make_bspline(
                [(15.561877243, -1.117477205), (15.538905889, -1.117072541), (15.493235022, -1.116268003), (15.425384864, -1.109228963), (15.358535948, -1.099015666), (15.292844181, -1.084023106), (15.22821477, -1.064779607), (15.164754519, -1.040723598), (15.101949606, -1.013526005), (15.040941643, -0.981490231), (14.982338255, -0.945848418), (14.926581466, -0.90723929), (14.873963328, -0.865864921), (14.824984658, -0.821317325), (14.779709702, -0.773660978), (14.73752952, -0.723403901), (14.699141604, -0.669844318), (14.663758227, -0.613958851), (14.633070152, -0.555375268), (14.606132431, -0.495363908), (14.582710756, -0.434053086), (14.56403794, -0.371237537), (14.549776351, -0.306956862), (14.539161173, -0.241316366), (14.533140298, -0.174113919), (14.532201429, -0.128840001), (14.531729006, -0.106058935)],
                knots=[0, 0, 0, 0, 1.028754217, 2.045334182, 3.052854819, 4.056607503, 5.061168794, 6.071104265, 7.095078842, 8.125279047, 9.155117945, 10.165957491, 11.161587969, 12.151493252, 13.128948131, 14.104219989, 15.088194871, 16.07871515, 17.064853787, 18.047899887, 19.02414258, 20.002704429, 20.980574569, 21.971845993, 22.979467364, 24, 24, 24, 24], degree=3))
            add(Edge.make_bspline(
                [(14.531729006, -0.106058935), (14.532136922, -0.083270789), (14.532951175, -0.037782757), (14.539984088, 0.029693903), (14.550016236, 0.096267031), (14.565893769, 0.161250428), (14.585004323, 0.225384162), (14.608672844, 0.28819452), (14.637130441, 0.349700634), (14.669352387, 0.409948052), (14.705561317, 0.468128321), (14.745265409, 0.523384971), (14.788512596, 0.575311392), (14.834706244, 0.624431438), (14.884410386, 0.670271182), (14.937599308, 0.712719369), (14.993748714, 0.752487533), (15.053032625, 0.788717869), (15.114536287, 0.820761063), (15.176697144, 0.849999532), (15.240338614, 0.873204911), (15.304274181, 0.893651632), (15.369629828, 0.908136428), (15.435604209, 0.919311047), (15.502423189, 0.926119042), (15.547171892, 0.926968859), (15.569589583, 0.92739459)],
                knots=[0, 0, 0, 0, 1.008818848, 2.013730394, 3.001654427, 3.987803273, 4.973046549, 5.963777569, 6.957074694, 7.972068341, 8.987420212, 9.989399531, 10.982630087, 11.977756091, 12.973280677, 13.973972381, 14.989194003, 16.018387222, 17.047741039, 18.059210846, 19.057554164, 20.045176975, 21.029480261, 22.018708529, 23.007435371, 24, 24, 24, 24], degree=3))
            add(Edge.make_bspline(
                [(15.569589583, 0.92739459), (15.606558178, 0.926328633), (15.679559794, 0.924223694), (15.786991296, 0.90770708), (15.890660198, 0.881374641), (15.991151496, 0.843648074), (16.089283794, 0.792144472), (16.184733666, 0.724303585), (16.277777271, 0.639516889), (16.335195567, 0.574496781), (16.365062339, 0.54067584)],
                knots=[0, 0, 0, 0, 0.96728863, 1.910097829, 2.838038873, 3.762875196, 4.71315279, 5.730631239, 6.819562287, 8, 8, 8, 8], degree=3))
            Line((16.365062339, 0.54067584), (16.365062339, 0.89213818))
        make_face()
        with BuildLine():
            add(Edge.make_bspline(
                [(15.589421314, 0.680599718), (15.553332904, 0.679373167), (15.481885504, 0.676944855), (15.377158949, 0.656214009), (15.276055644, 0.623727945), (15.180508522, 0.577258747), (15.091010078, 0.520613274), (15.011594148, 0.451988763), (14.942133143, 0.373616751), (14.88337512, 0.286205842), (14.836600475, 0.191902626), (14.803487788, 0.092501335), (14.782077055, -0.010391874), (14.7797139, -0.080613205), (14.778523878, -0.115974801)],
                knots=[0, 0, 0, 0, 1.026226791, 2.031711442, 3.026614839, 4.04107745, 5.047145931, 6.032893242, 7.017642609, 8.019221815, 9.021877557, 10.003543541, 10.994637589, 12, 12, 12, 12], degree=3))
            add(Edge.make_bspline(
                [(14.778523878, -0.115974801), (14.779094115, -0.142636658), (14.780215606, -0.195072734), (14.790998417, -0.272023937), (14.808426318, -0.345315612), (14.83312698, -0.414952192), (14.863732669, -0.481333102), (14.902226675, -0.544001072), (14.947523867, -0.603011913), (14.999269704, -0.657929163), (15.056294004, -0.707948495), (15.118144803, -0.751899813), (15.184738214, -0.787846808), (15.254436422, -0.818914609), (15.328930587, -0.841605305), (15.407147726, -0.858921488), (15.489641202, -0.868828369), (15.54587614, -0.870056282), (15.574547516, -0.870682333)],
                knots=[0, 0, 0, 0, 1.039728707, 2.044842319, 3.024901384, 3.974314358, 4.923051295, 5.871625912, 6.837440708, 7.820715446, 8.810779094, 9.792721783, 10.773906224, 11.758876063, 12.764959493, 13.806266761, 14.881525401, 16, 16, 16, 16], degree=3))
            add(Edge.make_bspline(
                [(15.574547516, -0.870682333), (15.603590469, -0.870079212), (15.660383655, -0.868899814), (15.743332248, -0.858761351), (15.821929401, -0.842401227), (15.896103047, -0.819173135), (15.966133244, -0.789534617), (16.031233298, -0.752027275), (16.092799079, -0.709312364), (16.148864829, -0.659488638), (16.199562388, -0.604578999), (16.243743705, -0.544829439), (16.281390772, -0.481139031), (16.312566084, -0.413514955), (16.336366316, -0.341431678), (16.35233117, -0.265069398), (16.363493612, -0.184793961), (16.364531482, -0.129787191), (16.365062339, -0.101651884)],
                knots=[0, 0, 0, 0, 1.121943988, 2.193949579, 3.223793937, 4.220241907, 5.192961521, 6.155822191, 7.11847367, 8.083710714, 9.04790392, 10.001595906, 10.949595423, 11.902125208, 12.873731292, 13.87582262, 14.913508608, 16, 16, 16, 16], degree=3))
            add(Edge.make_bspline(
                [(16.365062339, -0.101651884), (16.364009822, -0.06502357), (16.361953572, 0.006535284), (16.342548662, 0.110804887), (16.311261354, 0.208837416), (16.267381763, 0.300322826), (16.212395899, 0.384291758), (16.146167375, 0.459189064), (16.069838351, 0.525111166), (15.983628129, 0.580031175), (15.890876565, 0.624396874), (15.793824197, 0.657681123), (15.692615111, 0.676533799), (15.624017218, 0.679236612), (15.589421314, 0.680599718)],
                knots=[0, 0, 0, 0, 1.070913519, 2.092188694, 3.091357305, 4.074328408, 5.051968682, 6.018948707, 6.99050112, 7.9935919, 9.000589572, 9.992915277, 10.987769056, 12, 12, 12, 12], degree=3))
        make_face(mode=Mode.SUBTRACT)
    # profile 18 of 21: a face of its own
    with BuildSketch(Plane.XZ):
        with BuildLine():
            Line((18.409934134, 0.786368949), (18.163139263, 0.786368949))
            add(Edge.make_bspline(
                [(18.163139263, 0.786368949), (18.16474774, 0.819110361), (18.167906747, 0.883413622), (18.182700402, 0.97716812), (18.203868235, 1.066782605), (18.233797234, 1.151537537), (18.270966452, 1.232182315), (18.315540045, 1.308396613), (18.368335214, 1.379889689), (18.428211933, 1.445998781), (18.493244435, 1.506646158), (18.563413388, 1.559018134), (18.637148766, 1.603267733), (18.714226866, 1.640260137), (18.795517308, 1.668027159), (18.880282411, 1.688629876), (18.968894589, 1.701025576), (19.029268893, 1.702357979), (19.059974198, 1.703035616)],
                knots=[0, 0, 0, 0, 1.10065271, 2.161652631, 3.183658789, 4.190468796, 5.17591951, 6.163126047, 7.15150782, 8.156236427, 9.156009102, 10.134482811, 11.092018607, 12.041330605, 13.001268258, 13.972401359, 14.968799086, 16, 16, 16, 16], degree=3))
            add(Edge.make_bspline(
                [(19.059974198, 1.703035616), (19.090128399, 1.702329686), (19.149380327, 1.700942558), (19.235857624, 1.689030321), (19.318182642, 1.670373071), (19.396194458, 1.644196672), (19.469270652, 1.609008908), (19.537960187, 1.566739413), (19.603080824, 1.517852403), (19.661700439, 1.460295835), (19.715528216, 1.398851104), (19.761965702, 1.333253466), (19.801733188, 1.265501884), (19.834880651, 1.195079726), (19.859281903, 1.121323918), (19.877807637, 1.045308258), (19.888279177, 0.966245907), (19.889886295, 0.912733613), (19.890703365, 0.885527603)],
                knots=[0, 0, 0, 0, 1.111607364, 2.184268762, 3.212621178, 4.221274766, 5.211760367, 6.196651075, 7.1921475, 8.207485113, 9.220403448, 10.201281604, 11.166441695, 12.114753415, 13.065576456, 14.026450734, 14.996634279, 16, 16, 16, 16], degree=3))
            add(Edge.make_bspline(
                [(19.890703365, 0.885527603), (19.889372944, 0.847225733), (19.88673545, 0.771294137), (19.864174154, 0.65971103), (19.828937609, 0.551601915), (19.786511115, 0.464594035), (19.743711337, 0.394482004), (19.705142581, 0.336756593), (19.659991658, 0.274602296), (19.60760141, 0.208227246), (19.549055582, 0.137111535), (19.483823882, 0.061298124), (19.411441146, -0.018429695), (19.360638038, -0.072884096), (19.334313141, -0.101101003)],
                knots=[0, 0, 0, 0, 1.184426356, 2.348067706, 3.509069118, 4.696110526, 5.333549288, 6.050745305, 6.844228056, 7.710549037, 8.667450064, 9.695053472, 10.805634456, 12, 12, 12, 12], degree=3))
            Line((19.334313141, -0.101101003), (18.646262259, -0.835425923))
            Line((18.646262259, -0.835425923), (19.925959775, -0.835425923))
            Line((19.925959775, -0.835425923), (19.925959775, -1.117477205))
            Line((19.925959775, -1.117477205), (18.057370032, -1.117477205))
            Line((18.057370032, -1.117477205), (19.123876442, 0.020643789))
            add(Edge.make_bspline(
                [(19.123876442, 0.020643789), (19.149842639, 0.047749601), (19.199718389, 0.099814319), (19.270261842, 0.175826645), (19.333621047, 0.246344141), (19.390206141, 0.311233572), (19.43878961, 0.37144409), (19.481903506, 0.425025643), (19.516447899, 0.474332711), (19.553938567, 0.53148605), (19.590249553, 0.601267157), (19.621452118, 0.686543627), (19.64047807, 0.774329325), (19.642760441, 0.833652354), (19.643908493, 0.863492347)],
                knots=[0, 0, 0, 0, 1.329631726, 2.553950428, 3.673215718, 4.687767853, 5.603093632, 6.413772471, 7.123043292, 7.734684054, 8.834405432, 9.900288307, 10.943827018, 12, 12, 12, 12], degree=3))
            add(Edge.make_bspline(
                [(19.643908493, 0.863492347), (19.643408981, 0.882256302), (19.64242454, 0.919236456), (19.633736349, 0.973455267), (19.620606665, 1.025756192), (19.601792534, 1.076300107), (19.576958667, 1.124578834), (19.546729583, 1.17065114), (19.511851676, 1.215192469), (19.47150425, 1.256955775), (19.427180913, 1.295205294), (19.38035686, 1.329088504), (19.330817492, 1.357404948), (19.278771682, 1.380617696), (19.224364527, 1.398826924), (19.167490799, 1.411444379), (19.108307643, 1.419366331), (19.067895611, 1.42043818), (19.047303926, 1.420984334)],
                knots=[0, 0, 0, 0, 0.991446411, 1.95395049, 2.89581595, 3.838931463, 4.798493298, 5.75982156, 6.748411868, 7.785213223, 8.824556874, 9.840280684, 10.836137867, 11.835679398, 12.848801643, 13.863922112, 14.911575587, 16, 16, 16, 16], degree=3))
            add(Edge.make_bspline(
                [(19.047303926, 1.420984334), (19.025798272, 1.420422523), (18.983564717, 1.419319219), (18.921556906, 1.411601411), (18.862403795, 1.398286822), (18.805956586, 1.380076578), (18.752119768, 1.356930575), (18.701155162, 1.328101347), (18.653177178, 1.293700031), (18.608095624, 1.254696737), (18.56655964, 1.211272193), (18.530065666, 1.162864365), (18.498178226, 1.11035711), (18.470356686, 1.053892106), (18.447762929, 0.992956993), (18.430498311, 0.927768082), (18.416837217, 0.858608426), (18.41227338, 0.810848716), (18.409934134, 0.786368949)],
                knots=[0, 0, 0, 0, 1.031018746, 2.02475058, 2.990194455, 3.934040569, 4.864654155, 5.795059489, 6.735614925, 7.690564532, 8.649604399, 9.611025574, 10.590972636, 11.591080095, 12.624614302, 13.701020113, 14.821632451, 16, 16, 16, 16], degree=3))
        make_face()
    # profile 19 of 21: a face of its own
    with BuildSketch(Plane.XZ):
        with BuildLine():
            add(Edge.make_bspline(
                [(20.172754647, 0.256421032), (20.173012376, 0.300497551), (20.173513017, 0.386116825), (20.179082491, 0.510876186), (20.188334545, 0.627916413), (20.20101391, 0.737243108), (20.216443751, 0.838884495), (20.237041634, 0.932568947), (20.260465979, 1.018730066), (20.287614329, 1.097648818), (20.318247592, 1.170388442), (20.351588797, 1.238293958), (20.388961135, 1.301262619), (20.428228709, 1.360299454), (20.470981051, 1.414438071), (20.51600153, 1.464443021), (20.56504729, 1.50915861), (20.616451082, 1.549894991), (20.670678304, 1.58560529), (20.726183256, 1.617059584), (20.783347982, 1.643930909), (20.842328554, 1.665059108), (20.90259485, 1.682510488), (20.964357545, 1.694444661), (21.027718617, 1.701953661), (21.070486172, 1.702671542), (21.092175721, 1.703035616)],
                knots=[0, 0, 0, 0, 1.646270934, 3.197905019, 4.663502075, 6.030701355, 7.308322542, 8.50163776, 9.611534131, 10.641858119, 11.616356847, 12.558055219, 13.465016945, 14.349605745, 15.204443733, 16.039544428, 16.859896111, 17.680448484, 18.487036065, 19.28249412, 20.06191084, 20.843045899, 21.620316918, 22.403196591, 23.190181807, 24, 24, 24, 24], degree=3))
            add(Edge.make_bspline(
                [(21.092175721, 1.703035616), (21.114046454, 1.702652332), (21.157540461, 1.701890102), (21.221843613, 1.694564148), (21.28466122, 1.682408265), (21.345725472, 1.665184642), (21.405537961, 1.643816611), (21.463630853, 1.617033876), (21.520364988, 1.585857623), (21.574838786, 1.549224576), (21.627650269, 1.508381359), (21.67750224, 1.462210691), (21.724399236, 1.411178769), (21.768929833, 1.35583159), (21.80983066, 1.295107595), (21.848781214, 1.230062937), (21.883644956, 1.159560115), (21.917222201, 1.084775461), (21.946204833, 1.003639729), (21.972342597, 0.916610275), (21.993461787, 0.822659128), (22.011053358, 0.722279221), (22.024681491, 0.615101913), (22.034607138, 0.501356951), (22.039850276, 0.380969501), (22.040837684, 0.298659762), (22.041344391, 0.256421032)],
                knots=[0, 0, 0, 0, 0.810914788, 1.612654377, 2.396697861, 3.181598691, 3.963628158, 4.749916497, 5.551656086, 6.361998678, 7.18212741, 8.025565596, 8.878627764, 9.750805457, 10.657531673, 11.591944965, 12.560506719, 13.57287815, 14.630710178, 15.753379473, 16.941251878, 18.199788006, 19.531962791, 20.947069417, 22.433333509, 24, 24, 24, 24], degree=3))
            add(Edge.make_bspline(
                [(22.041344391, 0.256421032), (22.040832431, 0.214366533), (22.0398349, 0.132425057), (22.034665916, 0.012579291), (22.024484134, -0.100562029), (22.011747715, -0.20727025), (21.994107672, -0.307101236), (21.972417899, -0.400400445), (21.948335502, -0.487570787), (21.918608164, -0.567898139), (21.886071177, -0.642503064), (21.850670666, -0.71217011), (21.812744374, -0.777515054), (21.771424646, -0.838014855), (21.727382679, -0.894098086), (21.679675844, -0.944774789), (21.629648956, -0.991266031), (21.576682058, -1.032635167), (21.521358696, -1.068844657), (21.464819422, -1.101226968), (21.406061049, -1.127338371), (21.346415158, -1.14975876), (21.285028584, -1.166887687), (21.221977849, -1.17873143), (21.157583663, -1.187037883), (21.114053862, -1.187671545), (21.092175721, -1.187990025)],
                knots=[0, 0, 0, 0, 1.561518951, 3.042555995, 4.452378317, 5.7783523, 7.031515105, 8.214008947, 9.334062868, 10.386615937, 11.391082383, 12.354592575, 13.286541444, 14.194233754, 15.072674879, 15.931287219, 16.775624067, 17.606195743, 18.42308326, 19.229000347, 20.022332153, 20.807536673, 21.593273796, 22.3848459, 23.188221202, 24, 24, 24, 24], degree=3))
            add(Edge.make_bspline(
                [(21.092175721, -1.187990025), (21.070486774, -1.187623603), (21.027720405, -1.18690109), (20.964350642, -1.179426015), (20.902843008, -1.16740812), (20.842893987, -1.150580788), (20.784196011, -1.129983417), (20.727548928, -1.10314838), (20.672322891, -1.07224304), (20.61866524, -1.037046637), (20.567584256, -0.996722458), (20.518792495, -0.952121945), (20.473515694, -0.902132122), (20.431374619, -0.847542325), (20.39132355, -0.788854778), (20.354481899, -0.725268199), (20.3204048, -0.657034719), (20.289256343, -0.583713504), (20.261639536, -0.504234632), (20.237244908, -0.417688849), (20.217983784, -0.323312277), (20.201497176, -0.221862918), (20.188199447, -0.112904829), (20.179121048, 0.003621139), (20.173510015, 0.127642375), (20.173011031, 0.212711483), (20.172754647, 0.256421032)],
                knots=[0, 0, 0, 0, 0.810891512, 1.598919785, 2.382837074, 3.152667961, 3.926044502, 4.706494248, 5.493654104, 6.291793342, 7.103789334, 7.925228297, 8.761435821, 9.622817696, 10.50288917, 11.416980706, 12.369136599, 13.353924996, 14.394355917, 15.514179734, 16.714354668, 17.994756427, 19.357759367, 20.818452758, 22.365282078, 24, 24, 24, 24], degree=3))
        make_face()
        with BuildLine():
            add(Edge.make_bspline(
                [(20.419549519, 0.257522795), (20.41964337, 0.220791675), (20.419825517, 0.149503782), (20.42458396, 0.045912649), (20.431066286, -0.050706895), (20.439427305, -0.140477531), (20.451843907, -0.223095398), (20.465756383, -0.29912872), (20.482687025, -0.368175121), (20.502718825, -0.430708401), (20.525535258, -0.487789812), (20.550447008, -0.540905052), (20.577209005, -0.590681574), (20.607159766, -0.636672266), (20.639778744, -0.679027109), (20.674329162, -0.718495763), (20.712100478, -0.753693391), (20.764353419, -0.795907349), (20.833336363, -0.839529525), (20.920252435, -0.877515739), (21.009563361, -0.901387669), (21.0701822, -0.904423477), (21.100438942, -0.905938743)],
                knots=[0, 0, 0, 0, 1.459021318, 2.831673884, 4.118529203, 5.306027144, 6.411944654, 7.436330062, 8.375795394, 9.233974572, 10.042671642, 10.816086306, 11.563610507, 12.285937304, 12.993564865, 13.685989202, 14.367179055, 15.041617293, 16.353048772, 17.594441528, 18.799311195, 20, 20, 20, 20], degree=3))
            add(Edge.make_bspline(
                [(21.100438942, -0.905938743), (21.130891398, -0.904683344), (21.191733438, -0.902175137), (21.280624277, -0.87797613), (21.366919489, -0.841464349), (21.434547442, -0.798291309), (21.485998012, -0.757176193), (21.522861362, -0.722121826), (21.556695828, -0.682870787), (21.58878603, -0.640521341), (21.618218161, -0.594264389), (21.644982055, -0.544322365), (21.669404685, -0.490556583), (21.683318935, -0.453023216), (21.690432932, -0.433833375)],
                knots=[0, 0, 0, 0, 1.353760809, 2.704726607, 4.075137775, 5.516104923, 6.260822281, 7.007110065, 7.778089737, 8.566572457, 9.372053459, 10.217411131, 11.088608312, 12, 12, 12, 12], degree=3))
            add(Edge.make_bspline(
                [(21.690432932, -0.433833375), (21.698723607, -0.409295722), (21.715557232, -0.359473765), (21.737252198, -0.282188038), (21.754337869, -0.201100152), (21.769709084, -0.116694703), (21.780200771, -0.028349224), (21.788645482, 0.063662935), (21.793619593, 0.159411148), (21.794236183, 0.224464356), (21.794549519, 0.257522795)],
                knots=[0, 0, 0, 0, 0.884706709, 1.796334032, 2.740027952, 3.714592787, 4.726048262, 5.777819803, 6.87074269, 8, 8, 8, 8], degree=3))
            add(Edge.make_bspline(
                [(21.794549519, 0.257522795), (21.794117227, 0.290575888), (21.793271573, 0.355234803), (21.790039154, 0.449927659), (21.78169206, 0.539866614), (21.772421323, 0.625439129), (21.758752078, 0.706171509), (21.744013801, 0.782739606), (21.724212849, 0.85419484), (21.703061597, 0.92165594), (21.678853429, 0.984356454), (21.652205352, 1.042588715), (21.623745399, 1.096633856), (21.592833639, 1.146343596), (21.55983703, 1.191940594), (21.52388467, 1.232510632), (21.486402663, 1.269311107), (21.433903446, 1.311317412), (21.365173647, 1.354148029), (21.279652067, 1.393563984), (21.190653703, 1.416199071), (21.130488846, 1.419390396), (21.100438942, 1.420984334)],
                knots=[0, 0, 0, 0, 1.31362396, 2.569729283, 3.763502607, 4.902122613, 5.988968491, 7.01645872, 7.998833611, 8.933434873, 9.825090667, 10.667526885, 11.477055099, 12.250526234, 12.991942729, 13.710640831, 14.402115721, 15.076753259, 16.378508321, 17.609869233, 18.806226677, 20, 20, 20, 20], degree=3))
            add(Edge.make_bspline(
                [(21.100438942, 1.420984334), (21.070023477, 1.419388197), (21.009137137, 1.416193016), (20.919213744, 1.393648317), (20.833017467, 1.354352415), (20.764469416, 1.311175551), (20.711933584, 1.270052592), (20.674940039, 1.234391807), (20.640253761, 1.195384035), (20.608300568, 1.152639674), (20.578373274, 1.106702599), (20.550888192, 1.057211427), (20.526124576, 1.003915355), (20.503272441, 0.946859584), (20.483179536, 0.8843317), (20.466605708, 0.815370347), (20.451294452, 0.739578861), (20.440455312, 0.656513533), (20.430819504, 0.566720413), (20.424627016, 0.469859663), (20.419809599, 0.366094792), (20.419637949, 0.294438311), (20.419549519, 0.257522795)],
                knots=[0, 0, 0, 0, 1.207732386, 2.417664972, 3.655092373, 4.956220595, 5.625982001, 6.301752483, 6.994047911, 7.697131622, 8.419323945, 9.170223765, 9.943494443, 10.752040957, 11.610060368, 12.549350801, 13.567764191, 14.679664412, 15.874934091, 17.154273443, 18.533957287, 20, 20, 20, 20], degree=3))
        make_face(mode=Mode.SUBTRACT)
    # profile 20 of 21: a face of its own
    with BuildSketch(Plane.XZ):
        Polygon((22.872624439, 1.632522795), (23.38108798, 1.632522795), (23.38108798, -1.117477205), (23.134293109, -1.117477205), (23.134293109, 1.350471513), (22.711216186, 1.350471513), align=None)
    # profile 21 of 21: a face of its own
    with BuildSketch(Plane.XZ):
        with BuildLine():
            add(Edge.make_bspline(
                [(25.740513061, 0.414523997), (25.763022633, 0.402787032), (25.806923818, 0.37989603), (25.869448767, 0.343037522), (25.926589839, 0.30419105), (25.979932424, 0.265191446), (26.028539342, 0.224545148), (26.071867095, 0.182090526), (26.110985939, 0.138887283), (26.145106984, 0.094203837), (26.175118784, 0.048158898), (26.20105689, 0.000631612), (26.22322755, -0.048273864), (26.24079843, -0.099091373), (26.255272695, -0.151074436), (26.265232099, -0.204894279), (26.270588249, -0.260196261), (26.271600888, -0.297571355), (26.272113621, -0.316495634)],
                knots=[0, 0, 0, 0, 1.272397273, 2.481599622, 3.635517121, 4.734568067, 5.792894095, 6.808321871, 7.773003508, 8.711915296, 9.623354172, 10.525449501, 11.423591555, 12.311487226, 13.218079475, 14.126165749, 15.051214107, 16, 16, 16, 16], degree=3))
            add(Edge.make_bspline(
                [(26.272113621, -0.316495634), (26.271507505, -0.342972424), (26.270307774, -0.395379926), (26.259857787, -0.472730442), (26.244211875, -0.547853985), (26.221363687, -0.620734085), (26.191731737, -0.690968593), (26.155214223, -0.758617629), (26.113876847, -0.824789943), (26.080678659, -0.865505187), (26.063880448, -0.886107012)],
                knots=[0, 0, 0, 0, 1.025265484, 2.029385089, 3.018602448, 3.995076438, 4.983346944, 5.966715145, 6.97116228, 8, 8, 8, 8], degree=3))
            add(Edge.make_bspline(
                [(26.063880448, -0.886107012), (26.042008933, -0.910144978), (25.998536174, -0.957923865), (25.924063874, -1.019956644), (25.842332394, -1.072088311), (25.75365799, -1.114573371), (25.658277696, -1.147640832), (25.556211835, -1.17140281), (25.447261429, -1.18501329), (25.372378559, -1.18698071), (25.33396258, -1.187990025)],
                knots=[0, 0, 0, 0, 0.954267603, 1.896743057, 2.838368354, 3.796610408, 4.779680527, 5.799409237, 6.871065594, 8, 8, 8, 8], degree=3))
            add(Edge.make_bspline(
                [(25.33396258, -1.187990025), (25.297023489, -1.187084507), (25.22514377, -1.18532246), (25.120519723, -1.173383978), (25.022994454, -1.152462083), (24.932000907, -1.123827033), (24.848087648, -1.086576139), (24.771493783, -1.040212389), (24.701114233, -0.98660197), (24.639084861, -0.924205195), (24.58401537, -0.857374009), (24.535640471, -0.788426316), (24.495432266, -0.717355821), (24.461389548, -0.645222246), (24.435328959, -0.571014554), (24.417279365, -0.495114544), (24.405816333, -0.417654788), (24.404291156, -0.365379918), (24.403523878, -0.339081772)],
                knots=[0, 0, 0, 0, 1.256902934, 2.445805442, 3.576955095, 4.645999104, 5.686449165, 6.692658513, 7.68621702, 8.689161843, 9.678783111, 10.630372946, 11.551080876, 12.453998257, 13.34127905, 14.221779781, 15.105423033, 16, 16, 16, 16], degree=3))
            add(Edge.make_bspline(
                [(24.403523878, -0.339081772), (24.403977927, -0.319785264), (24.404875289, -0.281648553), (24.411086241, -0.22530551), (24.421071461, -0.170465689), (24.434632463, -0.116926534), (24.453011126, -0.06507782), (24.475201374, -0.014673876), (24.501076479, 0.034342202), (24.530997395, 0.082238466), (24.565806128, 0.128343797), (24.605220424, 0.173440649), (24.650028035, 0.216829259), (24.699730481, 0.259039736), (24.753759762, 0.300820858), (24.813519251, 0.339914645), (24.877424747, 0.37908876), (24.92284328, 0.402509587), (24.946142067, 0.414523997)],
                knots=[0, 0, 0, 0, 0.941657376, 1.861047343, 2.762797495, 3.66048619, 4.553285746, 5.444104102, 6.34607688, 7.256116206, 8.197091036, 9.162375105, 10.176350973, 11.237807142, 12.343728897, 13.50695164, 14.721116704, 16, 16, 16, 16], degree=3))
            add(Edge.make_bspline(
                [(24.946142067, 0.414523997), (24.914248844, 0.431915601), (24.852494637, 0.465590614), (24.770725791, 0.527463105), (24.700490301, 0.594474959), (24.643718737, 0.668041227), (24.599033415, 0.745863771), (24.56837594, 0.827455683), (24.547635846, 0.911304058), (24.545581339, 0.968587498), (24.544549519, 0.997356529)],
                knots=[0, 0, 0, 0, 1.166880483, 2.259407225, 3.286803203, 4.280235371, 5.237608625, 6.161067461, 7.076446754, 8, 8, 8, 8], degree=3))
            add(Edge.make_bspline(
                [(24.544549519, 0.997356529), (24.545834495, 1.026661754), (24.548417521, 1.085570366), (24.569304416, 1.173260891), (24.603341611, 1.259388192), (24.64963668, 1.343534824), (24.707298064, 1.422852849), (24.776477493, 1.493992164), (24.85552294, 1.556308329), (24.944039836, 1.608618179), (25.039296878, 1.651191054), (25.13980209, 1.680559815), (25.243804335, 1.699759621), (25.3145954, 1.701933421), (25.350489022, 1.703035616)],
                knots=[0, 0, 0, 0, 0.888701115, 1.786444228, 2.72001202, 3.692817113, 4.693886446, 5.687152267, 6.695133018, 7.739871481, 8.800368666, 9.853104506, 10.91144658, 12, 12, 12, 12], degree=3))
            add(Edge.make_bspline(
                [(25.350489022, 1.703035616), (25.385456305, 1.701899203), (25.454407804, 1.699658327), (25.555760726, 1.680968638), (25.652737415, 1.649752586), (25.74500345, 1.607404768), (25.83090706, 1.5552436), (25.906808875, 1.492071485), (25.973855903, 1.421245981), (26.02931507, 1.341952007), (26.075014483, 1.258128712), (26.10683662, 1.170425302), (26.127227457, 1.080736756), (26.129799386, 1.020049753), (26.13108798, 0.98964419)],
                knots=[0, 0, 0, 0, 1.072916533, 2.115669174, 3.151510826, 4.193348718, 5.225979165, 6.227137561, 7.216255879, 8.211077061, 9.189680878, 10.138522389, 11.067357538, 12, 12, 12, 12], degree=3))
            add(Edge.make_bspline(
                [(26.13108798, 0.98964419), (26.129960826, 0.959805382), (26.127747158, 0.901203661), (26.109125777, 0.81577568), (26.077765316, 0.73577265), (26.034948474, 0.660286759), (25.979142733, 0.590687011), (25.911093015, 0.526088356), (25.831341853, 0.465960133), (25.771422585, 0.43202799), (25.740513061, 0.414523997)],
                knots=[0, 0, 0, 0, 0.975232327, 1.915300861, 2.843280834, 3.77672583, 4.742871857, 5.749627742, 6.839139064, 8, 8, 8, 8], degree=3))
        make_face()
        with BuildLine():
            add(Edge.make_bspline(
                [(25.336716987, 1.420984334), (25.317427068, 1.420472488), (25.279687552, 1.419471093), (25.224350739, 1.414239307), (25.171729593, 1.404061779), (25.121274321, 1.390517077), (25.073676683, 1.372219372), (25.028290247, 1.350694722), (24.985887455, 1.324525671), (24.945956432, 1.295170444), (24.910009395, 1.26288316), (24.878105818, 1.22924381), (24.851605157, 1.193591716), (24.829101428, 1.156813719), (24.812773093, 1.117818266), (24.800543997, 1.077800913), (24.79227719, 1.036255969), (24.79165774, 1.007862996), (24.791344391, 0.993500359)],
                knots=[0, 0, 0, 0, 1.203892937, 2.355340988, 3.463153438, 4.544400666, 5.610487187, 6.640501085, 7.674077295, 8.714426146, 9.728707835, 10.68524104, 11.601827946, 12.495867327, 13.368432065, 14.231010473, 15.105153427, 16, 16, 16, 16], degree=3))
            add(Edge.make_bspline(
                [(24.791344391, 0.993500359), (24.791884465, 0.979137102), (24.792951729, 0.950753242), (24.801205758, 0.908838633), (24.813507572, 0.867650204), (24.832875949, 0.828167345), (24.856106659, 0.78902042), (24.884778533, 0.751187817), (24.918948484, 0.714537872), (24.957470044, 0.679382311), (24.999436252, 0.646461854), (25.043895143, 0.617882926), (25.090288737, 0.59397041), (25.138140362, 0.574068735), (25.187937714, 0.55859807), (25.239375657, 0.547622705), (25.292462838, 0.540801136), (25.328433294, 0.539986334), (25.346632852, 0.539574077)],
                knots=[0, 0, 0, 0, 0.873023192, 1.725219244, 2.590779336, 3.480155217, 4.391973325, 5.357036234, 6.360879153, 7.436073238, 8.526419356, 9.601555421, 10.645666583, 11.697338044, 12.750135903, 13.812665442, 14.89329948, 16, 16, 16, 16], degree=3))
            add(Edge.make_bspline(
                [(25.346632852, 0.539574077), (25.370007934, 0.540259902), (25.416527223, 0.541624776), (25.48510384, 0.554314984), (25.551781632, 0.574276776), (25.615847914, 0.601588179), (25.675644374, 0.635867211), (25.728947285, 0.67690744), (25.775301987, 0.72376123), (25.814226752, 0.775699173), (25.844405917, 0.830975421), (25.867900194, 0.886447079), (25.881619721, 0.942705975), (25.883409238, 0.980394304), (25.884293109, 0.999009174)],
                knots=[0, 0, 0, 0, 1.076279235, 2.141928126, 3.20205304, 4.278698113, 5.344010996, 6.36967002, 7.368914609, 8.37248503, 9.349703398, 10.264243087, 11.142681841, 12, 12, 12, 12], degree=3))
            add(Edge.make_bspline(
                [(25.884293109, 0.999009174), (25.883875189, 1.012074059), (25.883045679, 1.038005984), (25.876209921, 1.076300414), (25.864914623, 1.113723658), (25.849622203, 1.15058487), (25.829500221, 1.186366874), (25.805642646, 1.221632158), (25.776661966, 1.255587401), (25.744136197, 1.289023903), (25.707250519, 1.319968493), (25.666076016, 1.34718148), (25.620823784, 1.370291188), (25.571492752, 1.389060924), (25.518264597, 1.403158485), (25.461384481, 1.413715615), (25.40037813, 1.419665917), (25.358397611, 1.42053533), (25.336716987, 1.420984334)],
                knots=[0, 0, 0, 0, 0.814439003, 1.616544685, 2.417341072, 3.248991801, 4.09997495, 4.973547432, 5.9003056, 6.880240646, 7.880314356, 8.896779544, 9.951930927, 11.043077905, 12.18215768, 13.381699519, 14.647792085, 16, 16, 16, 16], degree=3))
        make_face(mode=Mode.SUBTRACT)
        with BuildLine():
            add(Edge.make_bspline(
                [(25.352692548, 0.257522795), (25.328236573, 0.257087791), (25.280259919, 0.25623442), (25.209972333, 0.246735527), (25.142516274, 0.233512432), (25.078119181, 0.213452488), (25.016808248, 0.187369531), (24.958251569, 0.155992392), (24.90289711, 0.118902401), (24.851509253, 0.076570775), (24.80458378, 0.030952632), (24.763413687, -0.017339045), (24.72845135, -0.06740675), (24.700296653, -0.119886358), (24.677187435, -0.173666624), (24.662012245, -0.230086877), (24.652283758, -0.288062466), (24.650977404, -0.327473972), (24.65031875, -0.347344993)],
                knots=[0, 0, 0, 0, 1.140299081, 2.23698856, 3.303958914, 4.344563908, 5.37730929, 6.408454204, 7.439741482, 8.480804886, 9.510774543, 10.48932336, 11.43758569, 12.353841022, 13.263987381, 14.161954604, 15.073269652, 16, 16, 16, 16], degree=3))
            add(Edge.make_bspline(
                [(24.65031875, -0.347344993), (24.651389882, -0.372040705), (24.653514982, -0.421036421), (24.67037377, -0.493450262), (24.697430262, -0.56355252), (24.73516436, -0.630771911), (24.781888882, -0.693589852), (24.839345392, -0.748345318), (24.903963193, -0.796997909), (24.97792865, -0.836346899), (25.058722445, -0.867771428), (25.146323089, -0.889422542), (25.239473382, -0.90375511), (25.303791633, -0.905199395), (25.336716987, -0.905938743)],
                knots=[0, 0, 0, 0, 0.898778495, 1.783155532, 2.693654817, 3.627872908, 4.583023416, 5.533784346, 6.509005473, 7.520592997, 8.575161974, 9.658835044, 10.801527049, 12, 12, 12, 12], degree=3))
            add(Edge.make_bspline(
                [(25.336716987, -0.905938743), (25.362449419, -0.905444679), (25.412584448, -0.904482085), (25.485723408, -0.895985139), (25.554744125, -0.882510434), (25.619512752, -0.862911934), (25.68075434, -0.838986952), (25.737430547, -0.808208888), (25.79099939, -0.773203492), (25.838821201, -0.731672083), (25.882375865, -0.687295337), (25.920352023, -0.640317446), (25.95331867, -0.592015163), (25.979192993, -0.541296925), (25.999877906, -0.489135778), (26.014746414, -0.435050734), (26.023920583, -0.378875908), (26.024848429, -0.340769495), (26.02531875, -0.321453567)],
                knots=[0, 0, 0, 0, 1.224942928, 2.386581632, 3.501229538, 4.569074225, 5.605009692, 6.626002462, 7.634866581, 8.645888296, 9.63523824, 10.59253846, 11.518950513, 12.414518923, 13.29783783, 14.186679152, 15.080837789, 16, 16, 16, 16], degree=3))
            add(Edge.make_bspline(
                [(26.02531875, -0.321453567), (26.024607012, -0.302692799), (26.023203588, -0.265699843), (26.014296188, -0.210883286), (25.998647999, -0.157923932), (25.977176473, -0.106184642), (25.948591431, -0.056713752), (25.914927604, -0.008222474), (25.874310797, 0.037943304), (25.828415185, 0.082142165), (25.77839743, 0.123011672), (25.725230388, 0.159165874), (25.669323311, 0.189613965), (25.610794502, 0.214376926), (25.549773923, 0.233852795), (25.486306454, 0.24745822), (25.420317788, 0.256022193), (25.375488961, 0.257016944), (25.352692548, 0.257522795)],
                knots=[0, 0, 0, 0, 0.917430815, 1.809013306, 2.70690318, 3.612392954, 4.541220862, 5.495268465, 6.494511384, 7.542276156, 8.608045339, 9.649016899, 10.681629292, 11.715607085, 12.752076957, 13.808767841, 14.885711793, 16, 16, 16, 16], degree=3))
        make_face(mode=Mode.SUBTRACT)
    extrude(amount=-CUT_EXTRUDE8_DEPTH, mode=Mode.SUBTRACT)


solid = part.part
